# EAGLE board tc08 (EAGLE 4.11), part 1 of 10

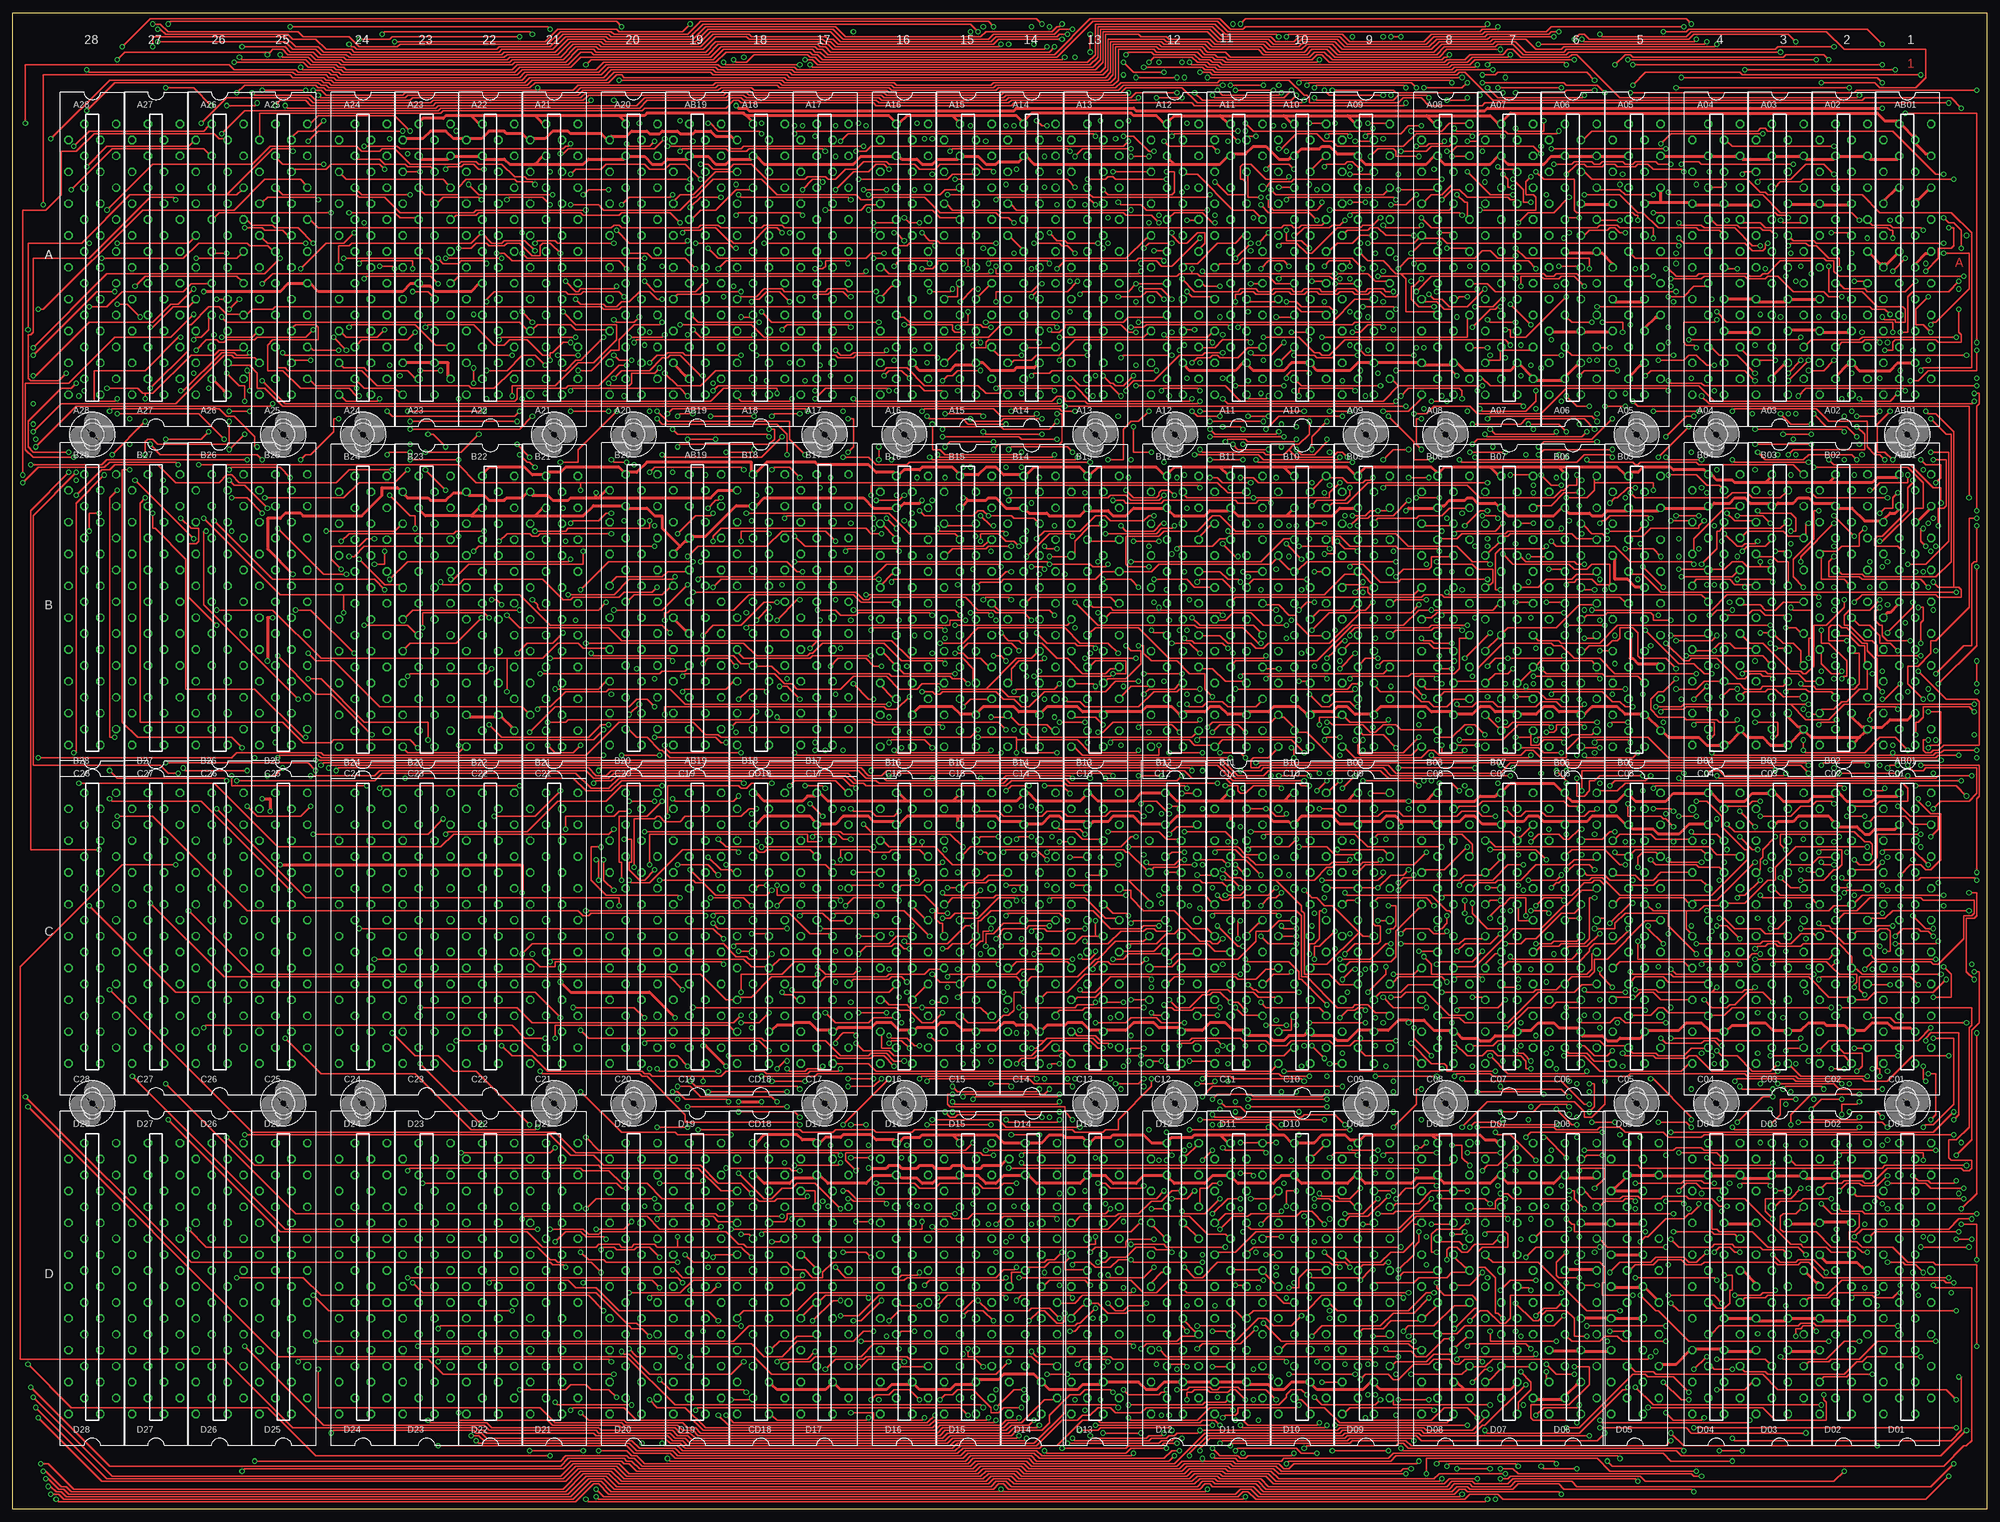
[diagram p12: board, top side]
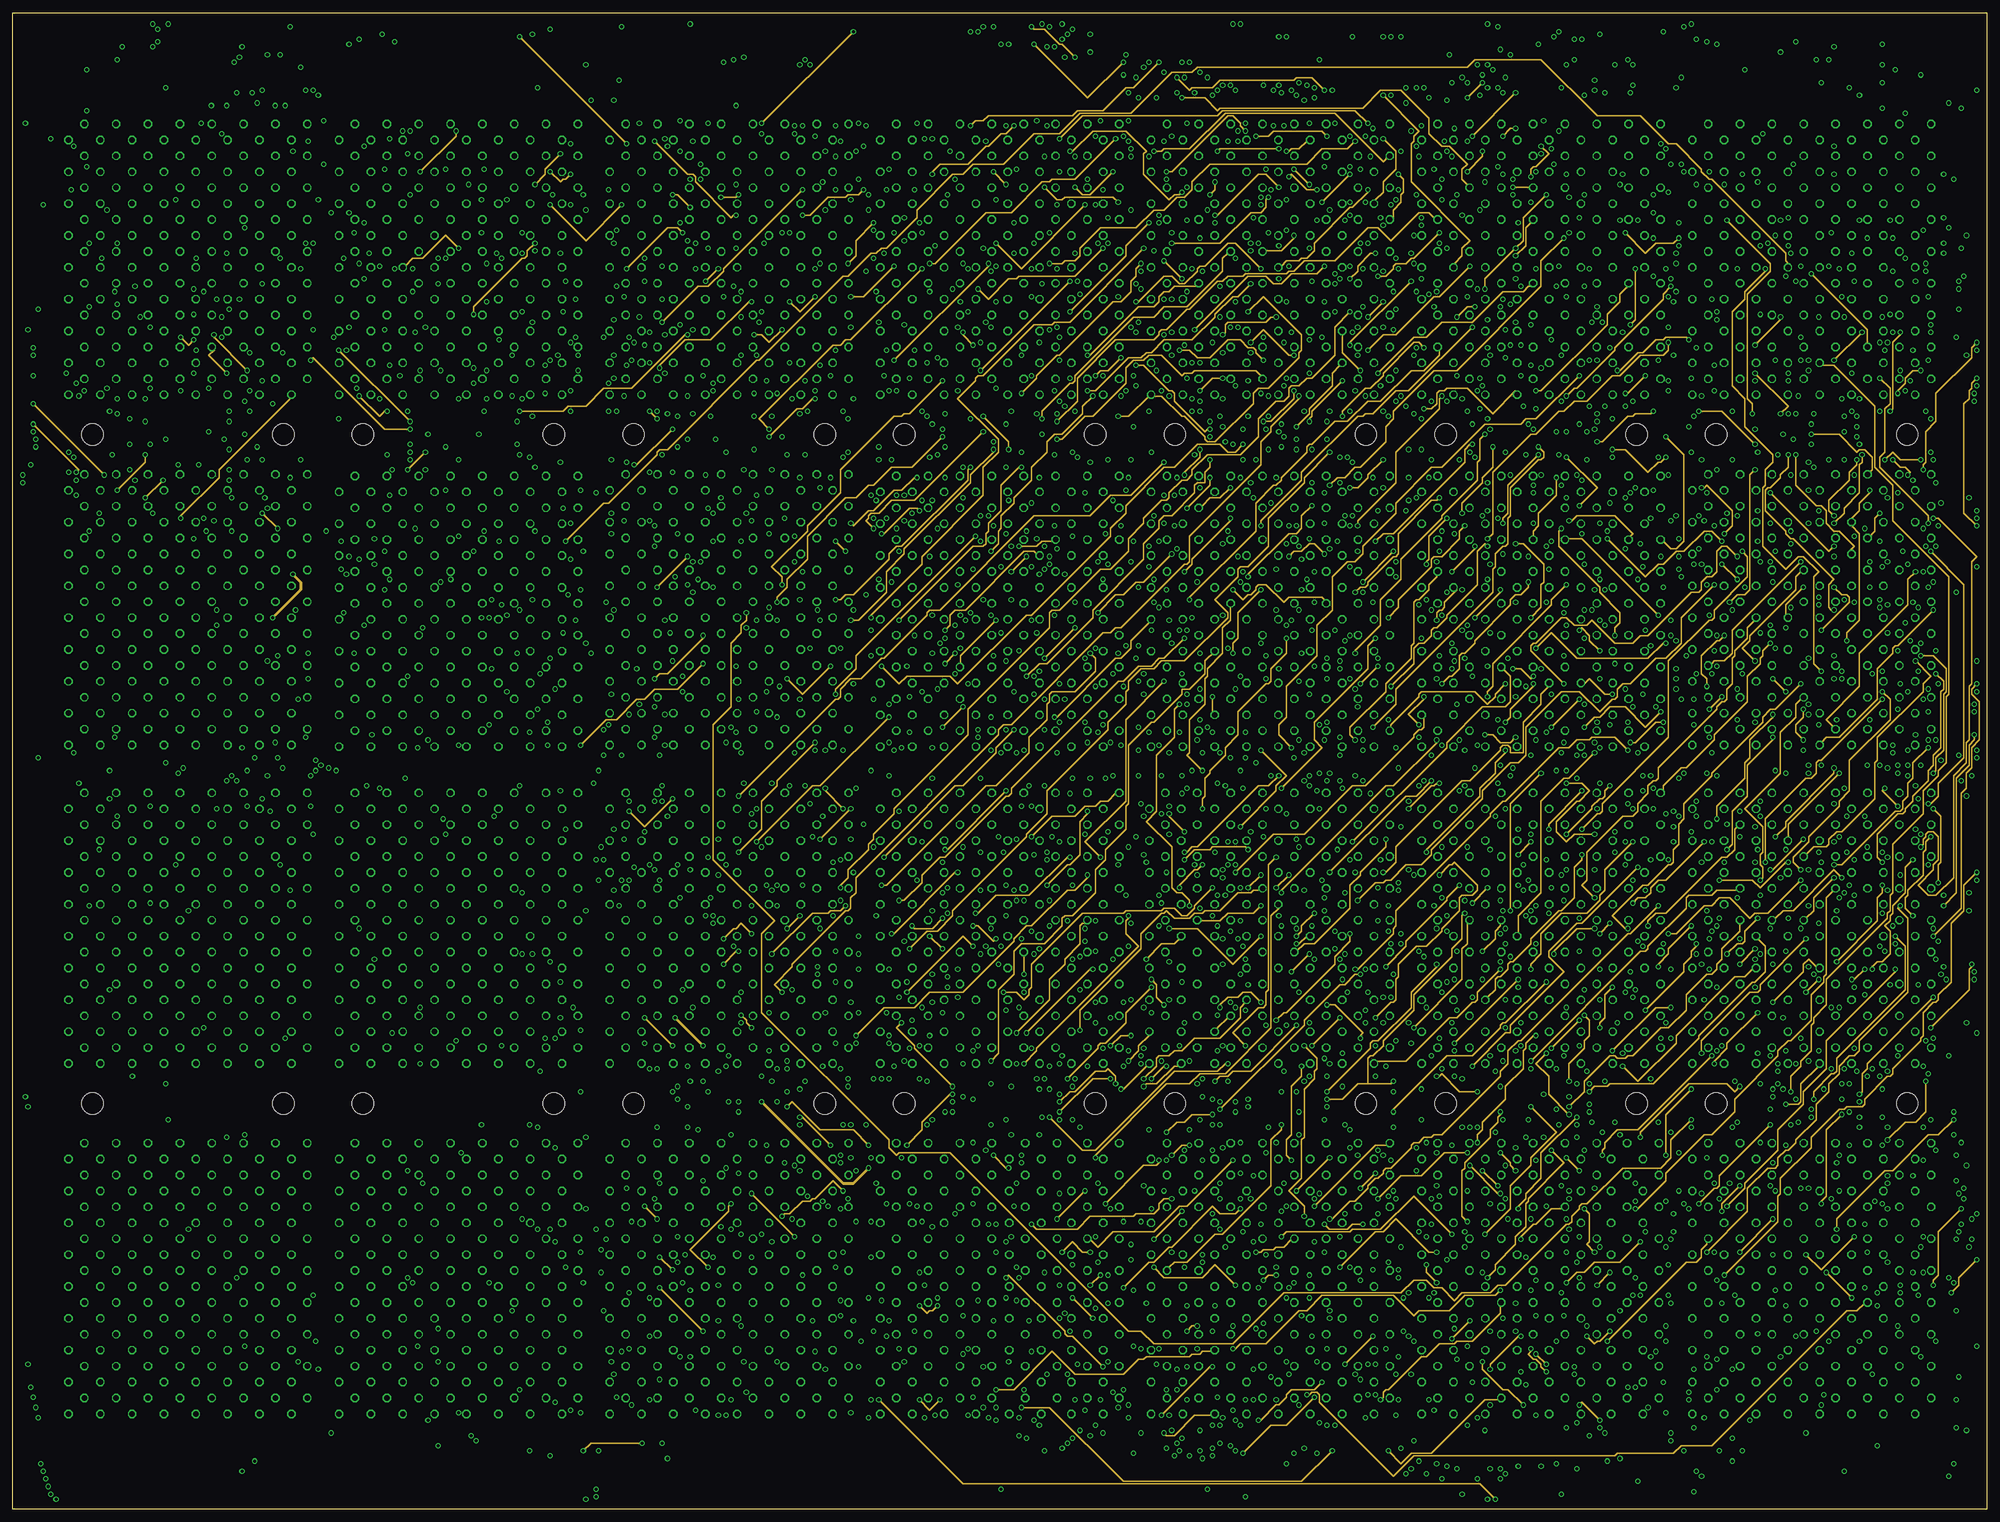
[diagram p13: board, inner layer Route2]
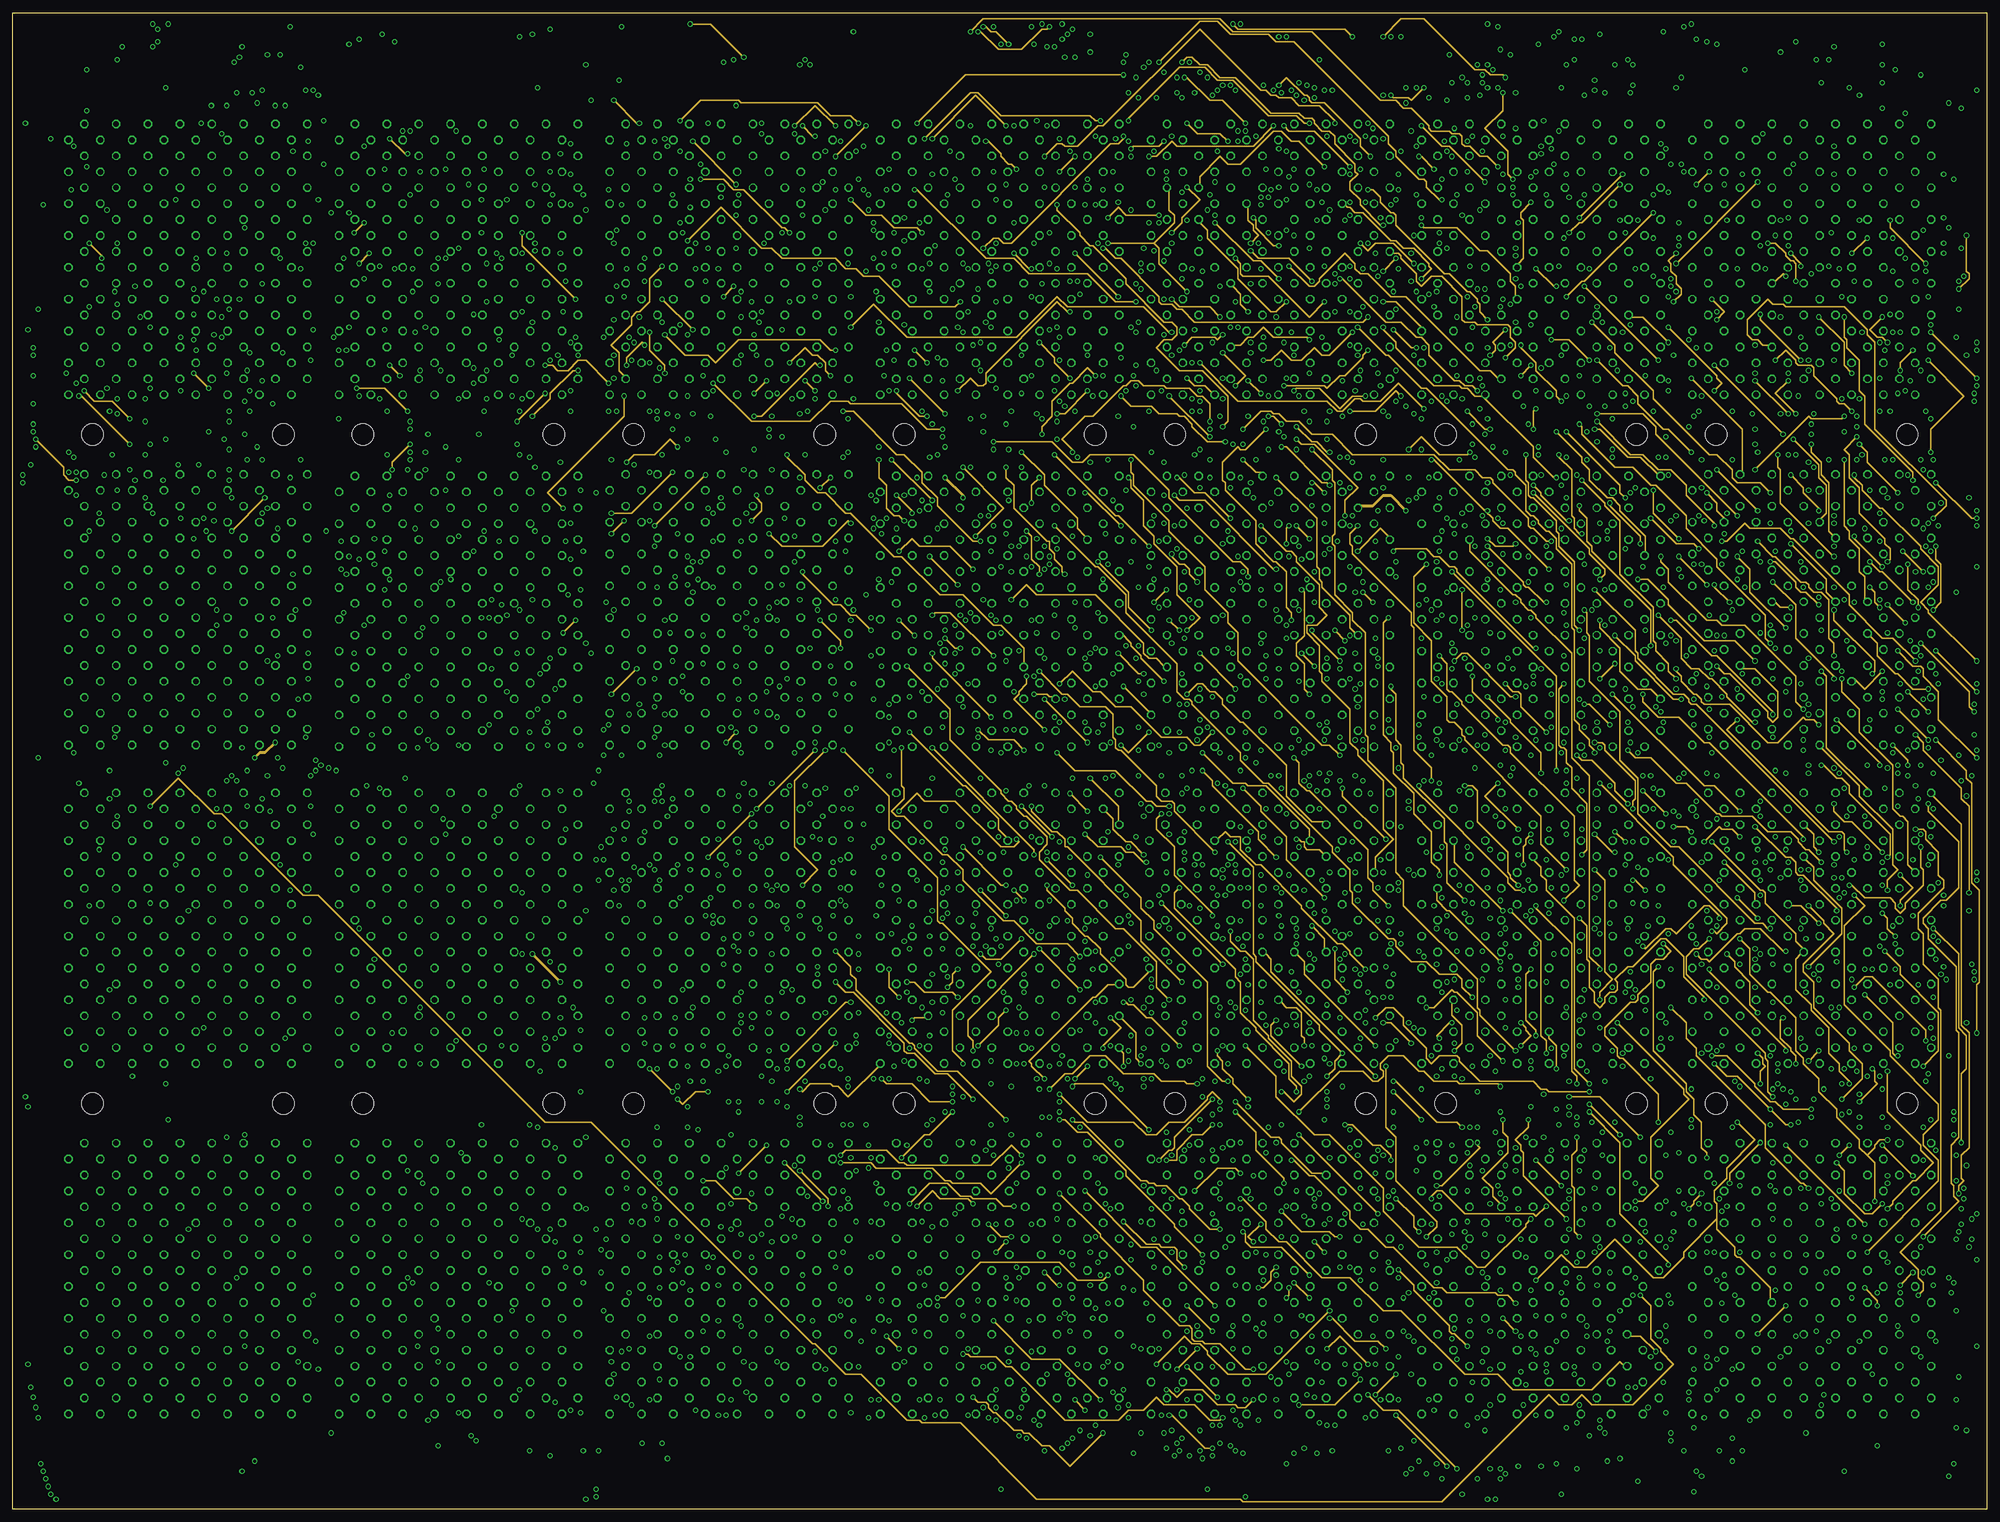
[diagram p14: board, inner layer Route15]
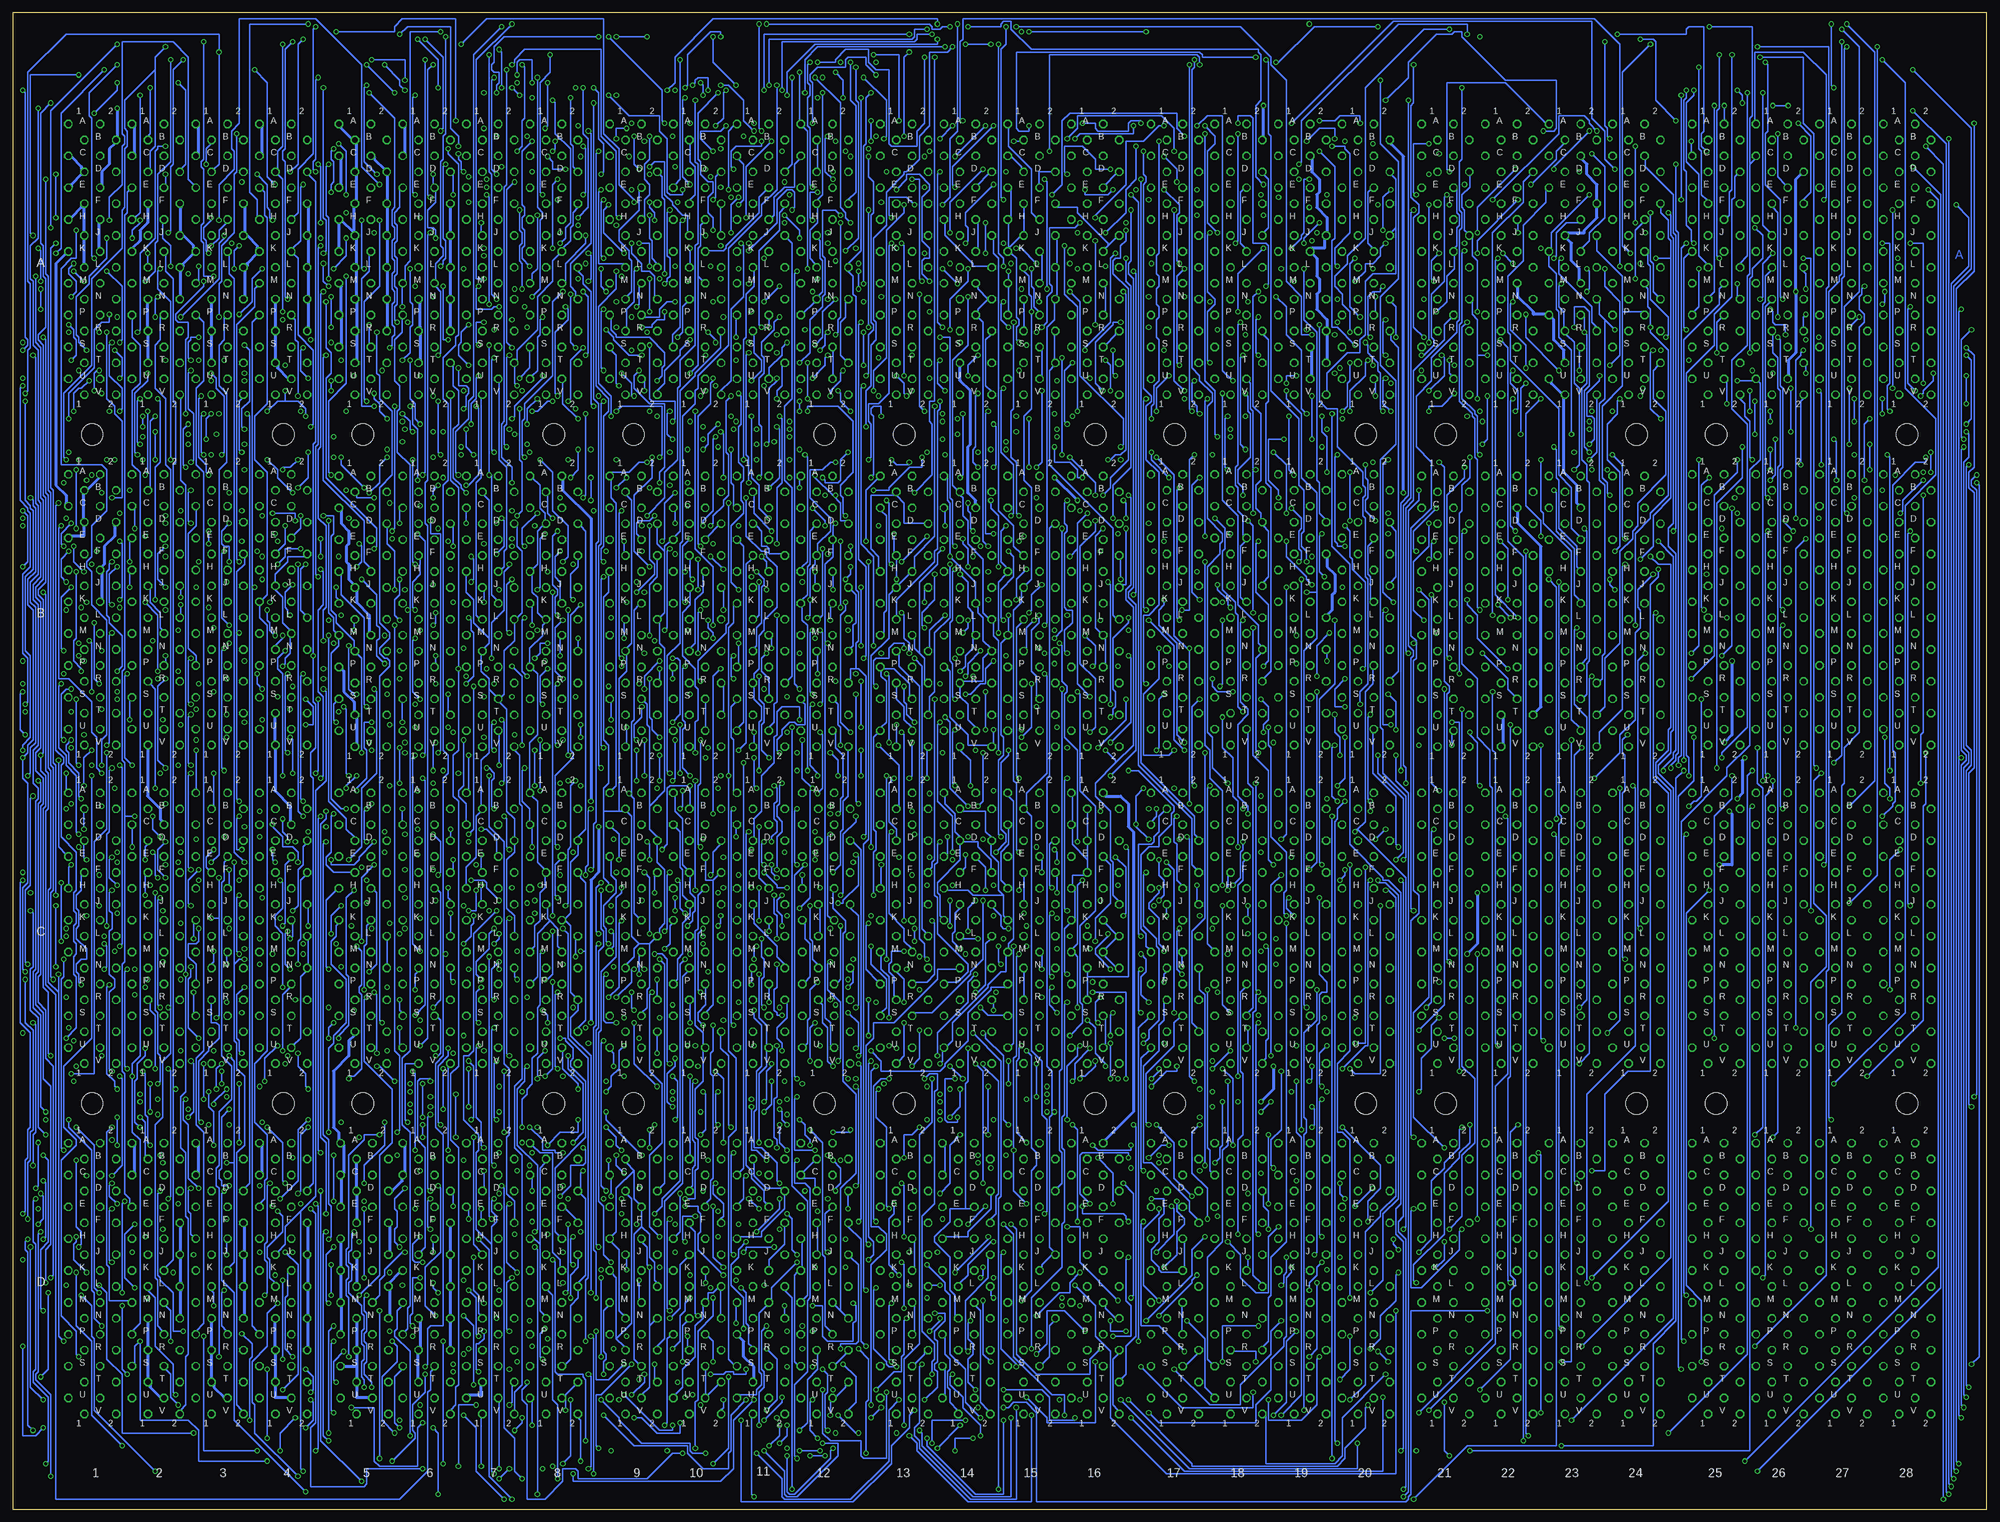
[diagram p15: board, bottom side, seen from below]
Size 393.76 x 298.44 mm. Coordinates in mm from the lower left corner, seen from the top.
Outline: 393.73,0 0,0 0.03,298.42 393.76,298.44 393.73,0
Copper layers (1*2*15*16): Top 0.035mm / dielectric 1.5mm / Route2 0.035mm / dielectric 0.15mm / Route15 0.035mm / dielectric 0.2mm / Bottom 0.035mm
Design rules "10mils": minimum track width 10mil, minimum drill 24mil, track to track 10mil, track to pad 10mil, pad to pad 10mil, via to via 10mil, smd to smd 10mil, copper to edge 40mil, drill to drill 10mil, minimum pad ring 10mil, minimum via ring 8mil, stop-mask expansion 0mil, vias tented up to drill 0mil, thermal gap 10mil
Net classes: 1 Power: width 0.635 mm, drill 0.381 mm, clearance 0.381 mm

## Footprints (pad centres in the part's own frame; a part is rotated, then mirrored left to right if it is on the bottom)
H807 = drill 1.092 octagon: A1 4.763,28.575; A2 -1.587,28.575; B1 1.587,25.4; B2 -4.763,25.4; C1 4.763,22.225; C2 -1.587,22.225; D1 1.587,19.05; D2 -4.763,19.05; E1 4.763,15.875; E2 -1.587,15.875; F1 1.587,12.7; F2 -4.763,12.7; H1 4.763,9.525; H2 -1.587,9.525; J1 1.587,6.35; J2 -4.763,6.35; K1 4.763,3.175; K2 -1.587,3.175; L1 1.587,0; L2 -4.763,0; M1 4.763,-3.175; M2 -1.587,-3.175; N1 1.587,-6.35; N2 -4.763,-6.35; P1 4.763,-9.525; P2 -1.587,-9.525; R1 1.587,-12.7; R2 -4.763,-12.7; S1 4.763,-15.875; S2 -1.587,-15.875; T1 1.587,-19.05; T2 -4.763,-19.05; U1 4.763,-22.225; U2 -1.587,-22.225; V1 1.587,-25.4; V2 -4.763,-25.4
H807-2 = drill 1.092 octagon: AA1 4.763,60.325; AA2 -1.587,60.325; AB1 1.587,57.15; AB2 -4.763,57.15; AC1 4.763,53.975; AC2 -1.587,53.975; AD1 1.587,50.8; AD2 -4.763,50.8; AE1 4.763,47.625; AE2 -1.587,47.625; AF1 1.587,44.45; AF2 -4.763,44.45; AH1 4.763,41.275; AH2 -1.587,41.275; AJ1 1.587,38.1; AJ2 -4.763,38.1; AK1 4.763,34.925; AK2 -1.587,34.925; AL1 1.587,31.75; AL2 -4.763,31.75; AM1 4.763,28.575; AM2 -1.587,28.575; AN1 1.587,25.4; AN2 -4.763,25.4; AP1 4.763,22.225; AP2 -1.587,22.225; AR1 1.587,19.05; AR2 -4.763,19.05; AS1 4.763,15.875; AS2 -1.587,15.875; AT1 1.587,12.7; AT2 -4.763,12.7; AU1 4.763,9.525; AU2 -1.587,9.525; AV1 1.587,6.35; AV2 -4.763,6.35; BA1 4.763,-9.525; BA2 -1.587,-9.525; BB1 1.587,-12.7; BB2 -4.763,-12.7; BC1 4.763,-15.875; BC2 -1.587,-15.875; BD1 1.587,-19.05; BD2 -4.763,-19.05; BE1 4.763,-22.225; BE2 -1.587,-22.225; BF1 1.587,-25.4; BF2 -4.763,-25.4; BH1 4.763,-28.575; BH2 -1.587,-28.575; BJ1 1.587,-31.75; BJ2 -4.763,-31.75; BK1 4.763,-34.925; BK2 -1.587,-34.925; BL1 1.587,-38.1; BL2 -4.763,-38.1; BM1 4.763,-41.275; BM2 -1.587,-41.275; BN1 1.587,-44.45; BN2 -4.763,-44.45; BP1 4.763,-47.625; BP2 -1.587,-47.625; BR1 1.587,-50.8; BR2 -4.763,-50.8; BS1 4.763,-53.975; BS2 -1.587,-53.975; BT1 1.587,-57.15; BT2 -4.763,-57.15; BU1 4.763,-60.325; BU2 -1.587,-60.325; BV1 1.587,-63.5; BV2 -4.763,-63.5
4,3 = hole 4.3: 0,0

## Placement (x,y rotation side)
A02  M903  [H807]  365.16,247.64 0 top
A03  M903  [H807]  352.46,247.64 0 top
A04  M903  [H807]  339.76,247.64 0 top
A05  M903  [H807]  323.89,247.64 0 top
A06  M903  [H807]  311.19,247.64 0 top
A07  M161  [H807]  298.49,247.64 0 top
A08  M206  [H807]  285.79,247.64 0 top
A09  M117  [H807]  269.91,247.64 0 top
A10  M113  [H807]  257.21,247.64 0 top
A11  M111  [H807]  244.51,247.64 0 top
A12  M113  [H807]  231.81,247.64 0 top
A13  H807  [H807]  215.94,247.64 0 top
A14  M302  [H807]  203.24,247.64 0 top
A15  M627  [H807]  190.54,247.64 0 top
A16  M602  [H807]  177.84,247.64 0 top
A17  H807  [H807]  161.96,247.64 0 top
A18  G888  [H807]  149.26,247.64 0 top
A20  G888  [H807]  123.86,247.64 0 top
A21  G888  [H807]  107.99,247.64 0 top
A22  M502  [H807]  95.29,247.64 0 top
A23  M633  [H807]  82.59,247.64 0 top
A24  W023  [H807]  69.89,247.64 0 top
A25  [H807]  54.01,247.64 0 top
A26  [H807]  41.31,247.64 0 top
A27  H807  [H807]  28.61,247.64 0 top
A28  H807  [H807]  15.91,247.64 0 top
AB01  G821  [H807-2]  377.86,215.89 0 top
AB19  W032  [H807-2]  136.56,215.89 0 top
B02  M623  [H807]  365.16,177.79 0 top
B03  M623  [H807]  352.46,177.79 0 top
B04  M623  [H807]  339.76,177.79 0 top
B05  M623  [H807]  323.89,177.47 0 top
B06  M111  [H807]  311.19,177.47 0 top
B07  M207  [H807]  298.49,177.47 0 top
B08  M113  [H807]  285.79,177.47 0 top
B09  M206  [H807]  269.91,177.47 0 top
B10  M627  [H807]  257.21,177.47 0 top
B11  M115  [H807]  244.51,177.47 0 top
B12  M117  [H807]  231.81,177.47 0 top
B13  M206  [H807]  215.94,177.47 0 top
B14  M206  [H807]  203.24,177.47 0 top
B15  M113  [H807]  190.54,177.47 0 top
B16  M602  [H807]  177.84,177.47 0 top
B17  H807  [H807]  161.96,177.79 0 top
B18  G888  [H807]  149.26,177.79 0 top
B20  G888  [H807]  123.86,177.79 0 top
B21  G879  [H807]  107.99,177.47 0 top
B22  M633  [H807]  95.29,177.47 0 top
B23  W005  [H807]  82.59,177.47 0 top
B24  H807  [H807]  69.89,177.47 0 top
B25  H807  [H807]  54.01,177.79 0 top
B26  H807  [H807]  41.31,177.79 0 top
B27  H807  [H807]  28.61,177.79 0 top
B28  H807  [H807]  15.91,177.79 0 top
C01  M101  [H807]  377.86,114.29 0 top
C02  M101  [H807]  365.16,114.29 0 top
C03  M101  [H807]  352.46,114.29 0 top
C04  M103  [H807]  339.76,114.29 0 top
C05  M103  [H807]  323.89,114.29 0 top
C06  M111  [H807]  311.19,114.29 0 top
C07  M207  [H807]  298.49,114.29 0 top
C08  M121  [H807]  285.79,114.29 0 top
C09  M206  [H807]  269.91,114.29 0 top
C10  M121  [H807]  257.21,114.29 0 top
C11  M113  [H807]  244.51,114.29 0 top
C12  M115  [H807]  231.49,114.29 0 top
C13  M111  [H807]  215.94,114.29 0 top
C14  M206  [H807]  203.24,114.29 0 top
C15  M113  [H807]  190.54,114.29 0 top
C16  M627  [H807]  177.84,114.29 0 top
C17  M111  [H807]  161.96,114.29 0 top
C19  H807  [H807]  136.56,114.29 0 top
C20  H807  [H807]  123.86,114.29 0 top
C21  H807  [H807]  107.99,114.29 0 top
C22  H807  [H807]  95.29,114.29 0 top
C23  H807  [H807]  82.59,114.29 0 top
C24  H807  [H807]  69.89,114.29 0 top
C25  H807  [H807]  54.01,114.29 0 top
C26  H807  [H807]  41.31,114.29 0 top
C27  H807  [H807]  28.61,114.29 0 top
C28  H807  [H807]  15.91,114.29 0 top
CD18  M228  [H807-2]  149.26,82.54 0 top
D01  H807  [H807]  377.86,44.44 0 top
D02  M903  [H807]  365.16,44.44 0 top
D03  M903  [H807]  352.46,44.44 0 top
D04  M903  [H807]  339.76,44.44 0 top
D05  M903  [H807]  323.57,44.44 0 top
D06  M903  [H807]  311.19,44.44 0 top
D07  M161  [H807]  298.49,44.44 0 top
D08  M207  [H807]  285.79,44.44 0 top
D09  M121  [H807]  269.91,44.44 0 top
D10  M119  [H807]  257.21,44.44 0 top
D11  M206  [H807]  244.51,44.44 0 top
D12  M627  [H807]  231.81,44.44 0 top
D13  M602  [H807]  215.94,44.44 0 top
D14  M307  [H807]  203.55,44.44 0 top
D15  M401  [H807]  190.54,44.44 0 top
D16  M302  [H807]  177.84,44.44 0 top
D17  M602  [H807]  161.96,44.44 0 top
D19  H807  [H807]  136.56,44.44 0 top
D20  H807  [H807]  123.86,44.44 0 top
D21  H807  [H807]  107.99,44.44 0 top
D22  H807  [H807]  95.29,44.44 0 top
D23  H807  [H807]  82.59,44.44 0 top
D24  H807  [H807]  69.89,44.44 0 top
D25  H807  [H807]  54.01,44.44 0 top
D26  H807  [H807]  41.31,44.44 0 top
D27  H807  [H807]  28.61,44.44 0 top
D28  H807  [H807]  15.91,44.44 0 top
U$17  [4,3]  54.01,214.3 0 top
U$18  [4,3]  69.89,214.3 0 top
U$19  [4,3]  107.99,214.3 0 top
U$20  [4,3]  123.86,214.3 0 top
U$66  [4,3]  161.96,214.3 0 top
U$67  [4,3]  177.84,214.3 0 top
U$68  [4,3]  215.94,214.3 0 top
U$69  [4,3]  231.81,214.3 0 top
U$70  [4,3]  269.91,214.3 0 top
U$71  [4,3]  285.79,214.3 0 top
U$72  [4,3]  323.89,214.3 0 top
U$73  [4,3]  339.76,214.3 0 top
U$74  [4,3]  377.86,214.3 0 top
U$75  [4,3]  377.86,80.95 0 top
U$76  [4,3]  339.76,80.95 0 top
U$77  [4,3]  323.89,80.95 0 top
U$78  [4,3]  285.79,80.95 0 top
U$79  [4,3]  269.91,80.95 0 top
U$80  [4,3]  231.81,80.95 0 top
U$81  [4,3]  215.94,80.95 0 top
U$82  [4,3]  177.84,80.95 0 top
U$83  [4,3]  161.96,80.95 0 top
U$84  [4,3]  107.99,80.95 0 top
U$85  [4,3]  69.89,80.95 0 top
U$86  [4,3]  123.86,80.95 0 top
U$87  [4,3]  54.01,80.95 0 top
U$88  [4,3]  15.91,80.95 0 top
U$90  [4,3]  15.91,214.3 0 top

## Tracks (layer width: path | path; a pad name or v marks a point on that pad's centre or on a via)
00\  (via drill 0.61)
  Top 0.254: v100.62,170.68 102.65,172.71 107.73,172.71 v109.76,174.74 | v111.29,196.58 111.8,197.09 116.88,197.09 118.4,198.62 v119.42,198.62 | v132.62,217.92 133.13,218.43 v135.67,218.43 | v296.2,267.7 296.71,267.2 299.76,267.2 A07.D1
  Route2 0.254: v149.39,276.34 v167.68,294.63
  Route15 0.254: v109.76,174.74 v112.3,177.28 | v119.42,198.62 123.48,198.62 v131.61,206.74 | v141.77,241.8 v143.8,243.83 | v191.04,294.63 193.58,297.17 240.83,297.17 243.37,294.63 259.12,294.63 272.83,280.91 275.88,280.91 277.4,279.39 278.93,279.39 282.48,275.83 282.48,275.32 282.99,274.82 286.55,274.82 287.06,274.31 288.58,274.31 289.09,273.8 289.09,272.28 289.6,271.77 290.61,271.77 292.64,269.74 294.17,269.74 v296.2,267.7
  Bottom 0.254: v100.62,170.68 95.54,165.6 95.54,163.56 94.02,162.04 B22.S2 | v112.3,177.28 114.34,179.31 114.34,188.96 111.29,192.01 v111.29,196.58 | v131.61,206.74 131.61,213.86 132.62,214.87 v132.62,217.92 | v135.67,218.43 136.69,219.44 136.69,231.13 139.74,234.18 139.74,239.76 v141.77,241.8 | v143.8,243.83 143.29,244.34 143.29,251.96 143.8,252.46 146.34,252.46 146.34,277.36 146.85,277.86 149.39,277.86 v149.39,276.34 | v167.68,294.63 v191.04,294.63
0_TO_AC\  (via drill 0.61)
  Top 0.254: v306.87,162.55 307.38,163.06 317.03,163.06 319.06,161.02 320.58,161.02 321.6,160.01 v323.12,160.01
  Bottom 0.254: v306.87,162.55 306.87,158.99 B06.T2 | v323.12,160.01 323.63,160.52 323.63,177.79 328.2,182.36 328.2,186.42 B05.H1
0_TO_DTB  (via drill 0.61)
  Top 0.254: v225.59,85.84 224.57,84.82 v220,84.82 | v208.82,81.27 208.32,80.76 188,80.76 v187.49,81.27 | v173.26,85.84 171.74,84.32 v166.66,84.32 | v161.58,88.38 161.07,87.87 158.53,87.87 158.02,87.36 154.98,87.36 v154.47,87.87 | v150.91,91.43 148.88,93.46 126.53,93.46 v126.02,92.95 | v123.99,128 123.99,137.66 128.05,137.66 128.56,138.16 129.07,138.16 130.08,137.15 133.13,137.15 134.15,138.16 145.32,138.16 146.85,139.69 v148.37,139.69 | v195.62,211.32 196.63,212.33 208.82,212.33 209.33,212.84 209.33,218.43 v208.32,218.43 | v246.92,244.34 248.96,244.34 A11.M1
  Route2 0.254: v225.59,85.84 228.13,88.38 228.13,89.9 228.64,90.41 230.67,90.41 231.68,91.43 233.21,91.43 235.75,93.97 240.83,93.97 244.89,98.03 244.89,100.06 245.91,101.08 C11.R1 | v220,84.82 220,86.35 218.48,87.87 217.97,87.36 215.94,87.36 211.87,83.3 210.86,83.3 v208.82,81.27 | v167.17,177.28 168.69,177.28 174.28,182.87 174.28,186.93 177.84,190.49 177.84,191.5 191.04,204.71 191.04,206.24 195.62,210.81 v195.62,211.32 | v214.41,223 215.94,223 222.54,229.6 225.08,229.6 226.1,230.62 227.11,230.62 229.65,233.16 235.24,233.16 239.81,237.73 239.81,238.24 243.37,241.8 244.38,241.8 v246.92,244.34
  Route15 0.254: v187.49,81.27 182.92,81.27 179.36,84.82 174.28,84.82 v173.26,85.84 | v148.37,139.69 v160.06,151.37 | v208.32,218.43 209.84,218.43 v214.41,223
  Bottom 0.254: v166.66,84.32 163.61,87.36 161.58,87.36 v161.58,88.38 | v154.47,87.87 v150.91,91.43 | v126.02,92.95 123.99,92.95 v123.99,128 | v160.06,151.37 162.09,153.4 162.09,172.2 v167.17,177.28
0_TO_DTB\  (via drill 0.61)
  Top 0.254: B10.L1 260.64,179.31 266.74,179.31 267.75,180.33 B09.K2 | v270.8,142.74 274.36,142.74 C09.A1 | v247.94,209.28 248.45,208.78 v267.24,208.78
  Bottom 0.254: 270.29,142.23 v270.8,142.74 | 270.29,142.23 269.78,141.72 269.78,118.86 268.77,117.84 C09.K2 | C09.A1 274.36,143.24 273.34,144.26 273.34,200.65 274.36,201.66 274.36,205.73 B09.A1 274.36,206.74 270.8,206.74 268.77,208.78 v267.24,208.78 | v247.94,209.28 247.94,233.16 247.43,233.67 247.43,242.3 245.91,243.83 245.91,246.88 A11.L1 | 270.29,142.23 270.29,156.96 269.78,157.47 269.78,179.31 268.77,180.33 B09.K2
0_TO_EF
  Bottom 0.254: A11.E2 243.37,263.13 244.89,261.61 244.89,258.56 251.5,251.96 251.5,251.45 252,250.94 255.05,250.94 A10.K2
0_TO_EF\  (via drill 0.61)
  Top 0.254: 287.06,236.72 287.06,239.26 285.53,239.26 284.01,240.78 281.47,240.78 A08.N2 | 287.06,236.72 287.06,235.7 A08.R1 | v244.38,235.7 244.89,236.21 267.24,236.21 267.75,236.72 287.06,236.72 | v278.93,274.82 285.02,274.82 286.55,276.34 290.1,276.34 A08.A1
  Bottom 0.254: v244.38,235.7 244.89,236.21 244.89,250.94 240.83,255 240.83,258.56 239.81,259.58 A11.F2 | v278.93,274.82 278.42,274.31 278.42,252.46 282.48,248.4 282.48,243.83 281.47,242.81 281.47,241.8 A08.N2
0_TO_LPB\  (via drill 0.61)
  Top 0.254: v228.64,31.99 230.16,30.47 v276.39,30.47 | v276.39,46.22 277.4,47.23 283.5,47.23 D08.K2
  Bottom 0.254: v228.64,31.99 228.64,33.01 225.59,33.01 225.08,33.52 225.08,48.76 226.6,50.28 D12.J2 | v276.39,30.47 v276.39,46.22 | D08.A1 290.1,72.63 288.58,71.11 286.04,71.11 286.04,51.3 284.52,49.77 284.52,48.25 D08.K2
0_TO_STA
  Top 0.254: A11.N1 246.42,240.78 252,240.78 A10.N2
0_TO_STA\  (via drill 0.61)
  Top 0.254: B11.P2 243.37,168.64 243.88,169.15 260.13,169.15 267.24,176.26 277.4,176.26 280.45,179.31 v282.99,179.31 295.18,179.31 296.2,180.33 B07.K2 | v302.8,150.36 302.3,149.85 283.5,149.85 v282.99,150.36 | v298.74,206.24 302.8,206.24 B07.A1 | v249.46,233.67 256.58,233.67 259.62,230.62 260.64,230.62 261.15,230.11 262.67,230.11 265.72,233.16 297.72,233.16 v298.74,232.14
  Bottom 0.254: v302.8,150.36 302.8,143.24 C07.A1 | v282.99,179.31 v282.99,150.36 | B07.K2 297.22,181.34 298.23,182.36 298.23,206.24 v298.74,206.24 v298.74,232.14 | v249.46,233.67 249.46,237.73 A11.P1
0_TO_STATE\  (via drill 0.61)
  Top 0.254: v143.8,112.26 144.31,112.76 174.79,112.76 176.31,114.29 C16.L1
  Bottom 0.254: v143.8,112.26 143.29,111.75 143.29,93.97 143.8,93.46 143.8,89.9 144.31,89.4 CD18.AV2
0_TO_W\  (via drill 0.61)
  Top 0.254: v145.32,54.85 146.85,54.85 147.36,54.34 CD18.BH2 | v145.32,97.02 148.88,97.02 v150.91,99.05 | v152.44,120.38 153.96,121.91 164.63,121.91 v165.14,121.4 | v165.14,129.53 165.14,131.56 170.72,131.56 171.23,131.05 174.79,131.05 175.3,131.56 180.88,131.56 181.9,130.54 C16.E1
  Bottom 0.254: v145.32,54.85 145.83,55.36 145.83,96.51 v145.32,97.02 | v150.91,99.05 152.44,100.57 v152.44,120.38 | v165.14,121.4 164.12,122.42 164.12,125.46 165.14,126.48 v165.14,129.53
01\  (via drill 0.61)
  Top 0.254: v79.79,242.81 82.84,242.81 83.86,241.8 A23.N1 | v79.79,247.38 79.79,248.91 69.63,248.91 v69.12,248.4 | v67.09,292.09 67.6,291.58 68.11,291.58 68.62,291.07 96.56,291.07 97.06,291.58 107.22,291.58 109.76,294.12 118.91,294.12 119.42,293.61 135.16,293.61 137.7,296.15 191.04,296.15 v192.57,294.63 | v297.22,266.18 298.23,265.16 298.23,263.64 v299.25,263.64
  Route2 0.254: v299.25,263.64 302.8,263.64 A07.E1
  Route15 0.254: v71.16,250.43 v69.12,248.4 | v192.57,294.63 193.08,294.63 196.63,291.07 201.2,291.07 205.27,295.14 206.28,295.14 v206.79,295.64 | v243.37,296.15 244.38,295.14 265.72,295.14 v267.24,293.61 | v273.34,293.61 276.9,297.17 281.47,297.17 291.63,287.01 293.66,287.01 294.68,285.99 297.22,285.99 v297.72,285.48
  Bottom 0.254: v79.79,242.81 79.28,243.32 79.28,246.88 v79.79,247.38 | v71.16,250.43 72.68,251.96 72.68,286.5 v67.09,292.09 | v206.79,295.64 208.32,295.64 208.82,295.14 210.35,295.14 210.35,295.64 210.86,296.15 v243.37,296.15 | v267.24,293.61 v273.34,293.61 | v297.72,285.48 298.23,284.98 298.23,267.2 v297.22,266.18
1_TO_DF  (via drill 0.61)
  Top 0.254: v238.29,4.05 237.78,3.54 197.65,3.54 | 197.65,3.54 v197.14,4.05 | v215.43,107.68 215.43,108.19 216.44,109.21 218.48,109.21 218.98,108.7 225.08,108.7 v226.1,109.72 | v288.07,262.12 289.6,260.59 290.1,260.59 290.1,257.54 A08.H1 | v286.55,290.06 286.04,289.55 285.53,289.55 285.02,289.04 263.18,289.04 261.66,290.56 259.62,290.56 258.61,289.55 242.86,289.55 241.84,290.56 238.29,290.56 237.27,291.58 229.14,291.58 228.64,292.09 219.49,292.09 219.49,285.99 218.48,284.98 154.47,284.98 153.96,285.48 121.96,285.48 121.45,285.99 120.43,285.99 118.91,284.47 104.18,284.47 103.16,283.45 63.03,283.45 62.52,283.96 61.5,283.96 61,284.47 20.36,284.47 v14.77,278.88 | v7.66,3.04 9.18,3.04 10.2,2.02 111.8,2.02 115.35,5.58 117.38,5.58 119.42,3.54 197.65,3.54
  Route2 0.254: v202.22,94.98 214.92,107.68 v215.43,107.68 | v226.1,109.72 229.14,112.76 231.68,112.76 232.7,113.78 C12.L1
  Bottom 0.254: v238.29,4.05 238.29,42.15 239.81,43.68 D11.L2 | v197.14,4.05 197.14,61.96 196.63,62.47 196.63,89.4 v202.22,94.98 | C12.J1 232.7,119.88 232.7,114.8 C12.L1 | v288.07,262.12 288.58,262.62 288.58,284.47 286.55,286.5 v286.55,290.06 | v14.77,278.88 8.16,272.28 8.16,3.54 v7.66,3.04
1_TO_DTF  (via drill 0.61)
  Top 0.254: v239.3,28.44 242.35,28.44 D11.S2 | v217.46,15.23 v225.08,15.23 | v177.84,29.45 177.33,29.96 170.72,29.96 169.2,28.44 v168.69,28.44 | v146.34,23.36 145.83,23.86 131.1,23.86 v129.07,25.9 | v127.04,34.53 125.51,36.06 123.48,36.06 122.97,36.56 85.38,36.56 v84.87,36.06 | v85.38,184.9 85.89,184.39 88.94,184.39 89.95,185.41 105.7,185.41 109.76,181.34 111.29,181.34 111.8,181.85 120.94,181.85 121.96,182.87 127.54,182.87 v128.56,183.88 | v134.66,189.98 136.69,192.01 150.4,192.01 153.45,195.06 162.09,195.06 v164.12,193.03 | v166.15,191 166.66,191.5 176.31,191.5 v176.82,191 | v193.58,181.34 194.09,181.85 198.66,181.85 v199.17,181.34
  Route2 0.254: v239.3,28.44 238.8,28.44 v229.14,18.78 | v128.56,183.88 v134.66,189.98 | v164.12,193.03 v166.15,191
  Route15 0.254: v217.46,15.23 210.86,8.62 206.79,12.69 205.27,12.69 202.73,15.23 201.71,15.23 201.2,15.74 199.68,15.74 196.12,19.29 195.62,19.29 194.6,20.31 194.6,20.82 194.09,21.32 192.57,21.32 v191.55,22.34 | v176.82,191 179.36,193.54 180.88,192.01 186.98,192.01 v191.55,187.44 | v199.17,181.34 202.22,184.39 204.25,182.36 215.94,182.36 225.59,172.71 225.59,170.68 226.6,169.66 228.13,169.66 229.65,168.14 B12.P2
  Bottom 0.254: v229.14,18.78 225.59,15.23 v225.08,15.23 | v191.55,22.34 187.49,18.28 187.49,17.26 177.84,17.26 v177.84,29.45 | v168.69,28.44 160.56,20.31 146.34,20.31 v146.34,23.36 | v129.07,25.9 127.04,27.93 v127.04,34.53 | v84.87,36.06 85.38,36.56 85.38,136.64 84.87,137.15 84.87,138.16 85.38,138.67 v85.38,184.9 | v191.55,187.44 193.58,185.41 v193.58,181.34
02\  (via drill 0.61)
  Top 0.254: v300.26,256.53 302.3,258.56 307.38,258.56 v310.42,261.61 | v309.92,288.02 309.41,288.53 294.68,288.53 v294.17,288.02 | v272.83,257.54 271.31,256.02 269.28,256.02 268.77,255.51 264.2,255.51 259.12,250.43 258.1,250.43 256.07,252.46 253.02,252.46 v252.51,251.96 | v81.32,266.69 A23.D2
  Route2 0.254: v88.43,274.82 88.43,273.8 v81.32,266.69
  Route15 0.254: v252.51,251.96 251.5,251.96 247.94,255.51 247.94,257.04 v247.43,257.54 | v242.35,272.78 240.83,274.31 236.26,274.31 v234.22,276.34 | v221.52,285.99 190.03,285.99 v180.38,276.34 | v168.69,276.34 167.17,277.86 163.1,277.86 160.56,280.4 145.32,280.4 144.82,280.91 137.2,280.91 v133.13,276.85 | v125,276.34 124.5,276.34 v119.92,280.91
  Bottom 0.254: v300.26,256.53 300.26,254.5 A07.J1 | v310.42,261.61 310.93,262.12 310.93,287.01 v309.92,288.02 | v294.17,288.02 293.66,288.53 293.66,289.04 291.63,291.07 276.39,291.07 276.39,273.8 273.34,270.75 273.34,258.05 v272.83,257.54 | v247.43,257.54 247.43,267.7 v242.35,272.78 | v234.22,276.34 234.22,284.47 234.73,284.98 234.73,285.99 233.21,287.52 227.62,287.52 227.62,289.04 227.11,289.55 223.56,289.55 223.56,288.02 v221.52,285.99 | v180.38,276.34 177.84,276.34 177.84,275.32 177.33,274.82 171.23,274.82 171.23,276.34 170.72,276.85 168.69,276.85 v168.69,276.34 | v133.13,276.85 130.08,276.85 129.07,277.86 125,277.86 v125,276.34 | v119.92,280.91 115.35,285.48 115.35,288.53 109.76,294.12 106.72,294.12 106.21,294.63 104.68,294.63 104.68,293.61 96.05,284.98 85.89,284.98 85.89,275.32 86.4,274.82 v88.43,274.82
03\  (via drill 0.61)
  Top 0.254: v280.96,256.02 280.45,255.51 273.85,255.51 v273.34,256.02 | v130.08,273.29 128.05,271.26 110.78,271.26 109.76,270.24 v109.26,270.24 | v104.18,264.15 103.67,264.66 100.62,264.66 100.11,265.16 90.46,265.16 88.94,263.64 88.94,262.12 82.33,262.12 81.32,263.13 A23.E2
  Route2 0.254: v211.87,289.55 209.33,292.09 208.82,292.09 205.78,295.14 203.74,295.14 v203.24,295.64 | v109.26,270.24 106.21,267.2 106.21,266.18 v104.18,264.15
  Route15 0.254: v280.96,256.02 281.47,255.51 288.07,255.51 292.64,250.94 294.17,250.94 298.74,246.37 298.74,244.84 299.76,243.83 299.76,241.8 A07.N1 | v273.34,256.02 272.83,256.02 268.77,260.08 268.77,261.1 266.74,263.13 266.74,264.66 268.26,266.18 267.75,266.69 267.75,268.21 263.69,272.28 263.69,273.8 262.67,274.82 261.15,274.82 259.62,276.34 259.62,276.85 259.12,277.36 257.59,277.36 256.58,278.37 250.99,278.37 243.88,285.48 240.83,285.48 238.29,288.02 236.76,288.02 235.24,289.55 234.22,289.55 v233.21,288.53 | v144.31,264.15 v135.67,272.78
  Bottom 0.254: v233.21,288.53 229.65,288.53 229.65,289.04 227.62,291.07 223.05,291.07 223.05,288.53 221.52,287.01 218.98,287.01 218.98,272.28 218.48,271.77 213.4,271.77 213.4,274.82 211.87,276.34 v211.87,289.55 | v203.24,295.64 196.63,295.64 196.63,296.15 196.12,296.66 194.6,296.66 194.6,295.14 190.54,291.07 145.32,291.07 145.32,290.56 144.82,290.06 144.82,280.91 145.83,279.9 145.83,265.67 v144.31,264.15 | v135.67,272.78 133.13,275.32 130.08,275.32 v130.08,273.29
04\  (via drill 0.61)
  Top 0.254: v76.24,292.6 106.21,292.6 108.75,295.14 120.43,295.14 120.94,294.63 133.64,294.63 v135.16,296.15 | v285.02,261.1 287.06,263.13 288.58,263.13 290.1,261.61 298.23,261.61 298.74,261.1 299.76,261.1 A07.F1
  Route2 0.254: v191.04,275.83 192.06,276.85 193.58,276.85 194.6,277.86 211.36,277.86 212.38,278.88 217.46,278.88 222.03,283.45 223.56,283.45 v228.64,288.53
  Route15 0.254: v78.78,270.24 78.27,270.24 v75.22,273.29 | v135.16,296.15 139.23,296.15 v145.83,289.55 | v228.64,288.53 236.76,296.66 240.32,296.66 242.86,294.12 250.48,294.12 252,292.6 255.56,292.6 274.36,273.8 274.36,272.28 275.88,270.75 275.88,269.74 280.45,265.16 281.47,265.16 281.98,264.66 281.98,263.64 284.52,261.1 v285.02,261.1
  Bottom 0.254: v78.78,270.24 76.24,267.7 76.24,257.54 79.28,254.5 79.28,252.97 80.81,251.45 A23.K2 | v75.22,273.29 75.73,273.8 75.73,275.32 76.24,275.83 v76.24,292.6 | v145.83,289.55 156.5,289.55 156.5,290.06 157.01,290.56 193.58,290.56 193.58,275.32 193.08,274.82 191.04,274.82 v191.04,275.83
05\  (via drill 0.61)
  Top 0.254: v249.46,216.9 v238.8,216.9 | v211.36,210.81 210.35,211.82 199.17,211.82 v198.66,211.32 | v193.58,217.92 193.08,218.43 v185.96,218.43 | v178.85,225.54 177.33,227.06 174.79,227.06 v173.77,226.05 | v174.28,231.13 173.77,230.62 167.68,230.62 167.17,230.11 165.14,230.11 v164.12,231.13 | v130.08,234.18 129.58,233.67 v122.97,233.67 | v120.43,243.83 119.92,243.32 113.32,243.32 112.81,242.81 112.3,242.81 v110.27,244.84 | v109.26,250.43 107.22,252.46 105.7,252.46 105.19,251.96 105.19,249.92 103.67,249.92 101.13,252.46 98.59,252.46 98.08,251.96 95.03,251.96 94.52,252.46 92.49,252.46 91.48,251.45 v88.94,251.45
  Route2 0.254: v272.32,226.56 279.44,233.67 281.98,233.67 285.02,236.72 291.12,236.72 297.22,242.81 301.28,242.81 302.3,243.83 302.8,243.83 A07.M1 | v255.56,223 255.56,221.48 250.99,216.9 v249.46,216.9 | v198.66,211.32 198.66,212.84 v193.58,217.92 | v88.94,251.45 86.4,253.99 81.82,249.42 79.79,249.42 78.27,247.89 A23.L2
  Route15 0.254: v269.78,221.98 267.24,221.98 264.7,219.44 260.64,223.51 256.07,223.51 v255.56,223 | v238.8,216.9 238.8,220.46 237.27,221.98 236.26,221.98 234.73,223.51 230.16,223.51 229.65,224.02 225.59,224.02 224.57,225.03 223.05,225.03 222.03,224.02 221.52,224.02 215.43,217.92 213.9,217.92 209.33,213.35 211.36,211.32 v211.36,210.81 | v185.96,218.43 v178.85,225.54 | v164.12,231.13 163.1,231.13 161.07,233.16 144.82,233.16 140.24,228.59 138.72,230.11 134.15,230.11 v130.08,234.18
  Bottom 0.254: v272.32,226.56 270.29,224.52 270.29,221.98 v269.78,221.98 | v173.77,226.05 174.28,226.56 v174.28,231.13 | v122.97,233.67 123.48,234.18 123.48,241.8 122.46,242.81 120.94,242.81 120.94,243.32 v120.43,243.83 | v110.27,244.84 110.78,245.35 110.78,248.91 v109.26,250.43
06\  (via drill 0.61)
  Top 0.254: v84.87,249.42 85.89,248.4 88.94,248.4 89.44,248.91 94.02,248.91 v94.52,248.4 | v96.56,250.43 98.08,250.43 99.6,248.91 120.94,248.91 v122.46,247.38 | v133.64,254.5 134.15,255 137.2,255 137.7,255.51 140.24,255.51 142.78,252.97 143.29,252.97 143.8,252.46 147.36,252.46 150.4,255.51 152.44,255.51 v153.45,254.5 | v177.84,257.54 178.85,256.53 v180.88,256.53 | v188.5,235.7 189.01,236.21 193.08,236.21 193.58,235.7 v195.11,235.7 | v196.12,240.78 196.12,242.81 203.24,242.81 204.76,244.34 v205.27,244.34 | v208.32,247.38 209.84,248.91 224.06,248.91 224.57,249.42 229.14,249.42 v229.65,248.91 | v233.21,245.35 235.75,242.81 244.38,242.81 244.89,243.32 247.94,243.32 248.45,242.81 250.99,242.81 251.5,243.32 255.05,243.32 255.56,242.81 257.08,242.81 257.59,243.32 260.64,243.32 261.15,242.81 263.69,242.81 264.2,243.32 267.75,243.32 268.26,242.81 269.78,242.81 270.29,243.32 273.34,243.32 273.85,242.81 v275.37,242.81 | v276.39,247.38 278.42,249.42 291.63,249.42 293.15,250.94 294.68,250.94 296.2,249.42 299.25,249.42 v299.76,249.92
  Route2 0.254: v122.46,247.38 130.59,255.51 132.62,255.51 v133.64,254.5 | v233.21,245.35 v229.65,248.91 | v299.76,249.92 301.79,251.96 301.79,255.51 302.8,256.53 A07.H1
  Route15 0.254: v155.99,275.83 160.06,279.9 v164.12,275.83
  Bottom 0.254: v84.87,249.42 85.38,248.91 85.38,246.37 78.78,239.76 78.78,236.72 77.76,235.7 A23.R2 | v96.56,250.43 v94.52,248.4 | v153.45,254.5 155.48,256.53 155.48,270.75 153.96,272.28 153.96,273.8 v155.99,275.83 | v164.12,275.83 165.14,275.83 168.18,272.78 171.74,272.78 171.74,264.15 177.84,258.05 v177.84,257.54 | v180.88,256.53 181.9,255.51 186.98,255.51 186.98,244.34 186.47,243.83 186.47,242.81 187.49,241.8 187.49,236.72 v188.5,235.7 | v195.11,235.7 196.63,237.22 196.63,240.27 v196.12,240.78 | v208.32,247.38 v205.27,244.34 | v275.37,242.81 276.39,243.83 v276.39,247.38
07\  (via drill 0.61)
  Top 0.254: v85.38,227.06 v81.32,227.06 | v104.18,252.46 104.68,252.97 108.24,252.97 108.75,252.46 v119.92,252.46 | v126.02,244.84 128.05,242.81 136.18,242.81 v138.21,244.84 | v140.75,247.38 142.28,248.91 160.56,248.91 v161.07,248.4 | v164.12,263.13 167.68,266.69 170.72,266.69 172.25,268.21 173.77,268.21 v174.79,267.2 | v274.86,293.61 v276.9,293.61 | v299.25,265.16 301.28,263.13 301.28,260.59 v302.8,260.59
  Route2 0.254: v91.98,238.24 91.98,239.76 101.64,249.42 102.14,249.42 102.65,249.92 102.65,250.94 v104.18,252.46 | v140.75,247.38 v138.21,244.84 | v183.42,266.18 183.42,266.69 184.95,268.21 190.54,268.21 194.09,271.77 194.6,271.77 197.14,274.31 198.16,274.31 v199.68,275.83
  Route15 0.254: v205.78,269.74 208.32,272.28 209.33,272.28 209.84,271.77 212.38,271.77 216.44,275.83 217.46,275.83 236.76,295.14 248.96,282.94 249.97,282.94 250.99,281.93 252,281.93 252.51,281.42 255.05,281.42 256.58,279.9 260.64,279.9 263.69,276.85 v263.69,276.34 | v297.22,282.44 297.22,278.88 293.66,275.32 298.23,270.75 298.23,266.18 v299.25,265.16 | v302.8,260.59 300.77,258.56 300.77,257.54 301.28,257.04 301.28,249.42 300.26,248.4 A07.L1
  Bottom 0.254: v81.32,227.06 81.32,231.13 A23.S2 | v85.38,227.06 91.98,233.67 v91.98,238.24 | v119.92,252.46 120.94,251.45 120.94,249.92 122.46,248.4 123.99,248.4 123.99,246.88 v126.02,244.84 | v161.07,248.4 161.58,248.91 161.58,258.05 161.07,258.56 161.07,260.08 v164.12,263.13 | v174.79,267.2 177.84,267.2 177.84,269.23 180.38,271.77 183.93,271.77 183.93,266.69 v183.42,266.18 | v205.78,269.74 v199.68,275.83 | v263.69,276.34 264.2,276.85 264.2,282.94 v274.86,293.61 | v276.9,293.61 295.69,293.61 297.72,291.58 297.72,288.53 298.23,288.02 298.23,287.01 297.72,286.5 296.71,286.5 296.71,284.47 297.22,283.96 v297.22,282.44
76  (via drill 0.61)
  Top 0.254: v309.41,90.41 313.47,90.41 316.52,87.36 332.78,87.36 334.3,88.89 C04.V2
  Bottom 0.254: v309.41,90.41 308.9,90.41 308.39,90.92 308.39,97.52 308.9,98.03 C06.S2
76+77  (via drill 0.61)
  Top 0.254: v356.65,125.46 361.22,125.46 363.26,127.5 363.76,127.5 364.78,128.51 364.78,131.56 360.72,131.56 v360.21,131.05
  Route2 0.254: v262.67,57.9 263.18,57.9 266.74,61.46 267.75,61.46 270.29,64 270.29,64.5 271.82,66.03 272.32,66.03 273.34,67.04 273.34,67.55 273.85,68.06 274.86,68.06 278.93,72.12 278.93,72.63 279.44,73.14 280.45,73.14 281.47,74.16 282.99,74.16 283.5,74.66 285.02,74.66 296.71,86.35 296.71,87.36 298.23,88.89 298.23,91.43 300.26,93.46 300.77,93.46 322.11,114.8 322.62,114.8 v328.2,120.38 | v330.24,114.8 331.76,114.8 337.35,120.38 338.87,120.38 340.4,121.91 342.43,121.91 346.49,117.84 347.51,118.86 350.05,118.86 v356.65,125.46
  Route15 0.254: v228.13,28.94 233.72,34.53 235.24,33.01 236.76,33.01 238.29,31.48 238.29,30.98 242.35,26.91 249.97,26.91 v262.67,39.61 | v360.21,131.05 359.19,132.07 359.19,134.61 357.67,136.13 C03.C1
  Bottom 0.254: v228.13,28.94 225.59,26.4 225.59,21.32 227.11,19.8 D12.V2 | v262.67,39.61 263.18,40.12 263.18,57.39 v262.67,57.9 | v328.2,120.38 330.24,118.35 v330.24,114.8
76\  (via drill 0.61)
  Top 0.254: v307.88,79.74 310.93,76.7 v311.95,76.7 | v311.95,49.26 316.52,49.26 317.54,48.25 317.54,45.2 317.03,45.2 317.03,42.66 v323.12,42.66 | v322.11,24.37 321.6,23.86 321.09,23.86 312.46,15.23 294.17,15.23 v293.66,15.74 | v292.14,18.28 290.1,20.31 285.53,20.31 282.99,17.77 270.29,17.77 v269.78,18.28 | v260.64,17.26 260.13,16.75 246.42,16.75 245.4,17.77 v243.88,17.77 | v234.22,28.44 233.72,28.94 230.67,28.94 D12.S2
  Route15 0.254: v307.88,87.87 307.88,92.44 306.36,93.97 306.36,94.48 C06.T2 | v311.95,74.16 311.95,71.62 310.93,70.6 310.93,64.5 311.44,64 311.44,55.36 v312.46,54.34 | v234.22,28.44 v240.32,22.34
  Bottom 0.254: D12.S2 229.65,28.94 227.62,30.98 227.62,31.48 D12.R2 | v307.88,79.74 v307.88,87.87 | v311.95,74.16 v311.95,76.7 | v312.46,54.34 313.98,52.82 313.98,49.77 313.47,49.26 v311.95,49.26 | v323.12,42.66 323.63,42.15 323.63,39.61 323.12,39.1 323.12,35.55 323.63,35.04 323.63,33.52 323.12,33.01 323.12,29.45 323.63,28.94 323.63,26.91 322.11,25.39 v322.11,24.37 | v293.66,15.74 292.14,17.26 v292.14,18.28 | v269.78,18.28 268.26,18.28 265.21,15.23 260.64,15.23 v260.64,17.26 | v243.88,17.77 240.32,21.32 v240.32,22.34
77
  Top 0.254: C06.U2 309.92,91.43 310.42,90.92 313.98,90.92 315.5,89.4 318.55,89.4 C05.V2
77\  (via drill 0.61)
  Top 0.254: v294.68,35.55 294.68,33.52 v307.88,33.52 | v307.88,9.13 307.38,9.64 284.52,9.64 v284.01,9.13 | v276.39,21.83 v282.48,21.83 | v255.56,11.16 255.05,10.66 246.42,10.66 245.91,10.15 244.89,10.15 244.38,10.66 240.83,10.66 v239.3,12.18
  Route2 0.254: v306.87,71.62 309.41,69.08 302.3,61.96 302.3,61.46 301.79,60.95 301.79,56.38 299.76,54.34 299.76,52.82 295.69,48.76 295.69,47.74 v294.17,46.22
  Route15 0.254: v239.3,12.18 237.78,12.18 231.18,18.78 v230.67,18.78
  Bottom 0.254: D12.T2 227.62,24.88 227.62,24.37 229.65,22.34 D12.U2 230.67,21.83 v230.67,18.78 | v306.87,71.62 306.87,88.38 C06.V2 | v294.17,46.22 295.18,45.2 295.18,36.06 v294.68,35.55 | v307.88,9.13 v307.88,33.52 | v284.01,9.13 282.48,10.66 v282.48,21.83 | v276.39,21.83 272.83,18.28 272.83,17.77 268.26,13.2 258.61,13.2 258.61,11.67 258.1,11.16 v255.56,11.16
+3V@A09U1  (via drill 0.61)
  Top 0.254: A08.F2 281.47,260.59 282.99,262.12 285.02,262.12 287.06,264.15 287.06,266.18 A08.D1 | 276.39,224.02 275.37,225.03 A09.U1 | v293.15,224.02 276.39,224.02 | A07.T2 294.17,229.1 296.71,229.1 296.71,231.13 A07.S2 297.22,231.13 302.8,231.13 A07.S1 | v222.03,172.2 223.05,171.18 225.08,171.18 225.08,168.64 222.03,165.6 218.48,165.6 217.97,165.09 B13.R1 | v224.06,224.02 241.84,224.02 244.89,220.97 273.34,220.97 276.39,224.02
  Bottom 0.254: A08.F2 280.96,259.58 281.98,258.56 281.98,256.02 282.48,255.51 282.48,252.97 284.01,251.45 A08.K2 284.52,250.43 286.04,248.91 286.04,244.84 289.09,241.8 289.09,235.19 293.15,231.13 293.15,229.1 A07.T2 293.66,228.08 293.66,224.52 v293.15,224.02 | B13.U2 214.41,155.94 215.94,157.47 215.94,160.01 217.46,161.53 217.46,164.07 B13.R1 | v222.03,172.2 222.03,189.98 224.57,192.52 224.57,223.51 v224.06,224.02
+3V@B12U1  (via drill 0.61)
  Top 0.254: B12.U1 235.24,153.91 203.24,153.91 202.22,154.93 B14.U2 | B13.D1 216.95,196.08 214.92,196.08 211.87,193.03 211.87,190.49 B13.F2 210.86,189.98 v206.79,189.98 | B13.K1 220,180.84 218.98,181.85 203.24,181.85 202.22,180.84 B14.K2
  Bottom 0.254: B14.U2 201.71,155.94 203.24,157.47 203.24,160.52 204.76,162.04 204.76,164.07 B14.R1 204.25,165.09 200.19,165.09 200.19,169.66 199.17,170.68 B14.N2 198.66,171.69 200.19,173.22 200.19,177.79 201.2,178.8 201.2,180.33 B14.K2 201.71,181.34 201.71,184.9 v206.79,189.98 206.79,200.65 207.3,201.16 207.3,205.73 B14.A1
+3V@C08U1  (via drill 0.61)
  Top 0.254: C08.U1 291.12,92.44 295.18,92.44 296.2,93.46 316.52,93.46 317.54,92.44 321.6,92.44 C05.U2 322.62,91.43 323.12,90.92 327.7,90.92 328.2,90.41 333.28,90.41 334.81,91.94 337.86,91.94 C04.U2 | C05.N2 319.57,108.19 320.58,109.21 333.28,109.21 334.3,108.19 C04.N2 | C02.C1 370.37,137.15 371.38,138.16 377.48,138.16 379,136.64 382.05,136.64 C01.C1 | 333.79,119.37 336.33,119.37 337.35,120.38 340.9,120.38 C04.J1 341.92,120.89 345.48,120.89 350.05,125.46 351.57,125.46 351.57,128 355.64,132.07 v369.86,132.07 | 333.79,119.37 327.19,119.37 326.17,120.38 C05.J1 | 333.79,119.37 333.79,115.81 334.81,114.8 C04.L2
  Bottom 0.254: C05.N2 319.06,108.7 319.06,113.78 C05.L2 | C04.L2 334.81,113.78 334.81,108.7 C04.N2 335.32,107.18 336.33,106.16 336.33,93.97 337.86,92.44 C04.U2 | v369.86,132.07 369.86,136.13 C02.C1
+3V@C15U1  (via drill 0.61)
  Top 0.254: v194.09,112.26 194.09,114.8 195.62,114.8 197.65,116.83 201.2,116.83 C14.K2 202.22,117.34 207.3,117.34 C14.K1 | C16.H2 176.82,123.94 177.33,124.45 180.88,124.45 181.9,125.46 193.58,125.46 194.6,126.48 198.16,126.48 C14.F2
  Bottom 0.254: v194.09,112.26 194.09,92.95 194.6,92.44 C15.U1 | C14.D1 204.76,134.1 205.78,135.12 205.78,138.67 207.81,140.7 207.81,142.23 C14.A1 | C14.D1 204.25,133.08 201.2,133.08 201.2,132.07 198.66,129.53 198.66,127.5 C14.F2 | C14.K1 208.32,117.84 208.82,118.35 208.82,122.42 209.33,122.92 209.33,124.96 204.76,129.53 204.76,132.58 C14.D1
+3V@D09U1  (via drill 0.61)
  Top 0.254: v294.68,20.82 275.37,20.82 275.37,21.83 D09.U1 | D07.T2 294.17,25.9 294.68,25.9 296.71,27.93 D07.S2 297.22,28.44 302.8,28.44 D07.S1
  Bottom 0.254: v294.68,20.82 294.17,21.32 294.17,24.88 D07.T2
+3V@D10U1
  Top 0.254: D11.K2 243.37,47.74 248.96,47.74 D11.K1 249.46,47.23 252,44.69 D10.L2 | D11.D1 245.91,62.98 245.91,58.92 241.84,58.92 240.32,57.39 D11.F2 | D14.M1 208.82,41.14 211.87,41.14 213.4,42.66 252,42.66 253.53,41.14 255.05,41.14 D10.M2
  Bottom 0.254: D10.N2 252.51,38.6 252.51,43.68 D10.L2 253.02,44.18 254.04,43.17 255.05,43.17 255.05,41.64 D10.M2 256.07,40.63 256.07,38.09 257.59,36.56 257.59,30.47 260.13,27.93 260.13,24.37 261.66,22.85 D10.U1 | D11.F2 239.81,56.38 239.81,52.82 242.86,49.77 242.86,48.25 D11.K2
-15V  (via drill 0.61)
  Top 0.635: 116.88,201.66 118.4,203.19 B20.B2 | 116.37,201.66 111.29,201.66 110.78,201.16 107.73,201.16 106.72,202.17 103.67,202.17 B21.B2 102.65,202.68 101.64,201.66 98.59,201.66 98.08,201.16 95.03,201.16 94.02,202.17 90.97,202.17 B22.B2 89.95,202.68 87.92,202.68 86.4,201.16 83.35,201.16 82.84,201.66 78.78,201.66 78.27,202.17 B23.B2 77.25,203.19 76.74,203.7 73.7,203.7 73.7,202.17 69.63,198.11 57.95,198.11 57.44,198.62 54.39,198.62 53.38,197.6 50.84,197.6 50.84,191.5 v55.92,186.42 | 116.37,201.66 116.88,201.66 | 116.88,201.66 139.23,201.66 140.75,203.19 B18.B2 | AB01.AF2 373.42,261.1 375.45,263.13 375.96,263.13 AB01.AE2 | A23.B2 78.27,273.29 81.82,273.29 83.35,274.82 86.4,274.82 87.92,273.29 89.95,273.29 A22.B2 90.97,273.29 93.51,273.29 95.03,274.82 98.08,274.82 98.59,274.31 101.64,274.31 102.65,273.29 A21.B2 103.67,273.29 106.21,273.29 107.73,274.82 110.78,274.82 111.29,274.31 117.38,274.31 118.4,273.29 A20.B2 119.42,273.8 122.46,273.8 123.48,274.82 126.53,274.82 127.04,274.31 129.07,274.31 129.58,274.82 132.62,274.82 133.13,274.31 135.67,274.31 136.18,274.82 139.23,274.82 140.24,273.8 143.29,273.8 143.8,273.29 A18.B2 | v372.91,279.39 294.17,279.39 293.66,278.88 224.06,278.88 223.56,279.39 200.19,279.39 199.68,278.88 146.85,278.88 146.34,279.39 144.82,279.39 v144.31,279.9 | 116.37,201.66 v116.37,202.68 | v170.72,68.06 174.28,68.06 174.79,68.57 176.82,68.57 177.33,68.06 180.38,68.06 180.88,68.57 183.42,68.57 183.93,68.06 186.98,68.06 187.49,68.57 189.52,68.57 190.03,68.06 193.08,68.06 193.58,68.57 197.14,68.57 198.16,69.58 D14.B2
  Top 0.635: v144.82,81.27 v149.39,81.27 | v142.28,88.38 138.21,92.44 v137.7,92.44 | v132.12,98.03 127.04,103.11 111.29,103.11 v109.26,105.14 | v101.64,122.92 101.64,128.51 v53.38,128.51 | v51.34,139.18 51.34,141.72 v49.82,141.72 | v50.84,169.15 50.84,177.79 v51.85,177.79
  Route2 0.635: v170.72,68.06 167.68,65.01 165.64,65.01 v149.39,81.27 | v132.12,98.03 v137.7,92.44 | v51.85,177.79 57.44,183.38 57.44,184.9 v55.92,186.42
  Route15 0.635: v103.67,110.73 v109.26,105.14 | v48.3,149.85 49.31,150.86 50.33,150.86 v52.36,152.9
  Bottom 0.635: AB01.AE2 375.96,264.15 375.96,266.69 374.43,268.21 374.43,271.26 373.42,272.28 AB01.AB2 372.91,273.8 v372.91,279.39 | v144.31,279.9 144.31,273.8 A18.B2 | v116.37,202.68 116.37,269.74 118.91,272.28 A20.B2 | v144.82,81.27 142.28,83.81 v142.28,88.38 | v103.67,110.73 101.64,112.76 v101.64,122.92 | v53.38,128.51 50.84,128.51 50.84,138.67 v51.34,139.18 | v49.82,141.72 48.8,142.74 48.8,149.34 v48.3,149.85 | v52.36,152.9 50.84,154.42 v50.84,169.15
ADDR_ACC  (via drill 0.61)
  Top 0.254: v191.55,81.78 192.06,82.28 208.32,82.28 v208.82,82.79 | v240.83,81.27 241.84,80.25 244.89,80.25 245.91,79.24 v256.58,79.24 | v296.71,84.32 297.22,83.81 308.9,83.81 v310.42,82.28 | v344.46,84.32 344.97,83.81 v351.06,83.81
  Route2 0.254: v324.65,74.16 324.65,75.17 334.3,84.82 341.92,84.82 343.44,83.3 v344.46,84.32 | v353.6,80.76 356.14,80.76 356.65,81.27 356.65,84.82 360.21,88.38 C02.V2
  Route15 0.254: v164.12,105.14 166.15,103.11 167.68,103.11 177.84,92.95 177.84,91.43 178.34,90.92 179.87,90.92 183.93,86.86 186.47,86.86 v191.55,81.78 | v208.82,82.79 214.41,77.2 223.56,77.2 226.1,74.66 228.13,74.66 230.67,77.2 233.72,77.2 238.29,81.78 238.29,82.28 239.3,83.3 240.83,81.78 v240.83,81.27 | v256.58,79.24 264.7,87.36 269.28,87.36 271.31,85.33 272.32,85.33 273.34,86.35 273.34,87.36 272.83,87.87 272.83,88.89 274.36,90.41 277.4,90.41 280.45,87.36 281.47,87.36 283.5,85.33 288.07,85.33 288.58,84.82 296.2,84.82 v296.71,84.32 | v310.42,82.28 316.52,82.28 v324.65,74.16
  Bottom 0.254: v164.12,105.14 164.12,106.67 163.61,107.18 C17.N1 | v351.06,83.81 353.6,81.27 v353.6,80.76
ADDR_ACC\  (via drill 0.61)
  Top 0.254: v178.34,105.14 177.33,106.16 175.3,106.16 174.79,105.65 167.68,105.65 167.17,105.14 C17.P1 | v188.5,102.1 189.52,103.11 v197.65,103.11
  Route2 0.254: v197.65,103.11 200.19,103.11 201.71,101.59 202.73,102.6 202.73,103.62 203.24,104.13 203.24,108.7 213.4,118.86 221.52,118.86 222.03,119.37 229.14,119.37 229.65,119.88 231.68,119.88 233.21,118.35 234.22,118.35 235.75,119.88 235.75,120.38 v239.3,123.94 | v243.88,126.99 251.5,134.61 257.59,134.61 267.24,144.26 269.78,144.26 279.44,153.91 279.44,154.42 280.45,155.44 280.96,155.44 281.47,155.94 281.47,157.98 B08.T2
  Route15 0.254: v178.34,105.14 179.87,105.14 181.9,103.11 187.49,103.11 v188.5,102.1
  Bottom 0.254: v239.3,123.94 241.34,123.94 241.34,124.45 v243.88,126.99
B-BRK  (via drill 0.61)
  Top 0.254: v238.29,155.94 239.3,156.96 250.99,156.96 B10.T2 253.02,157.98 253.53,157.98 255.56,155.94 B10.U2 256.07,154.93 258.1,154.93 263.69,149.34 v384.59,149.34
  Bottom 0.254: v238.29,155.94 238.29,64.5 235.24,61.46 235.24,42.66 236.26,41.64 D12.M1 | v384.59,149.34 384.59,132.07 383.07,130.54 C01.E1 | B10.R2 252,164.07 252,158.99 B10.T2 | B10.S2 255.56,161.02 255.56,155.94 B10.U2
B-BRK\  (via drill 0.61)
  Top 0.254: B02.M2 364.27,174.23 366.3,174.23 368.34,172.2 369.35,172.2 369.35,168.64 B02.P1 369.86,167.63 369.86,163.56 368.34,163.56 365.8,161.02 364.78,161.02 363.26,159.5 360.72,159.5 B02.T2 359.7,158.48 v358.18,158.48 | B02.J1 366.3,184.39 365.29,185.41 360.72,185.41 360.72,189.98 B02.F2 360.72,191 363.76,191 364.78,192.01 368.34,192.01 368.34,194.55 v369.35,195.57 | v358.18,148.32 357.67,148.83 298.74,148.83 296.71,146.8 275.88,146.8 274.36,148.32 248.96,148.32 248.45,147.82 246.92,147.82 246.92,149.34 247.43,149.85 250.48,149.85 252,151.37 B10.V2
  Bottom 0.254: B02.M2 363.76,175.25 364.27,175.76 364.27,178.8 366.3,180.84 366.3,183.88 B02.J1 | v369.35,195.57 369.35,199.63 B02.C1 | v358.18,148.32 358.68,148.83 358.68,157.98 v358.18,158.48
B-RUN  (via drill 0.61)
  Top 0.254: v365.29,7.61 363.26,5.58 325.66,5.58 324.65,6.59 298.74,6.59 298.23,6.08 v296.71,6.08 | v294.68,8.12 v288.07,8.12 | v267.75,26.91 v254.54,26.91 | v204.76,74.66 v199.17,74.66 | v199.17,84.32 198.66,84.82 v195.11,84.82
  Route2 0.254: v195.11,89.4 196.63,90.92 196.63,103.62 199.68,106.67 199.68,111.24 201.2,112.76 205.78,112.76 209.33,116.32 209.33,117.84 209.84,118.35 211.36,118.35 215.94,122.92 215.94,127.5 217.97,129.53 217.97,131.56 222.03,135.62 222.03,140.2 222.54,140.7 222.54,152.39 227.11,156.96 227.62,156.96 233.21,162.55 233.21,163.56 234.73,163.56 237.78,166.61 237.78,169.15 B11.N2
  Route15 0.254: v379.51,135.62 381.04,135.62 381.54,135.12 381.54,133.59 384.08,131.05 384.08,126.48 385.1,125.46 385.1,123.94 380.02,118.86 380.02,115.81 381.04,114.8 381.04,108.7 384.08,105.65 384.08,100.06 384.59,99.56 384.59,59.42 376.46,51.3 380.02,47.74 380.02,46.22 381.04,45.2 381.04,43.68 v380.02,42.66 | v288.07,8.12 276.39,19.8 273.34,19.8 v270.29,22.85 | v247.43,27.93 245.91,27.93 240.83,33.01 237.78,33.01 237.27,33.52 235.75,33.52 235.24,34.02 235.24,36.06 234.73,36.56 232.7,36.56 225.59,43.68 225.59,45.71 216.95,54.34 216.95,54.85 v208.82,62.98
  Bottom 0.254: v379.51,135.62 379.51,139.18 C01.B1 | v380.02,42.66 377.99,40.63 377.99,34.53 377.48,34.02 377.48,19.8 v365.29,7.61 | v296.71,6.08 v294.68,8.12 | v270.29,22.85 267.75,25.39 v267.75,26.91 | v254.54,26.91 252,26.91 251.5,27.42 249.97,27.42 249.97,26.91 247.43,26.91 v247.43,27.93 | v208.82,62.98 206.79,65.01 206.79,72.63 v204.76,74.66 | v199.17,74.66 v199.17,84.32 | v195.11,84.82 v195.11,89.4
B-XSTA  (via drill 0.61)
  Top 0.254: v240.83,65.01 239.3,65.01 238.29,64 236.76,64 236.76,60.95 D12.E1 | v245.91,99.56 244.38,101.08 v242.86,101.08 240.83,103.11 239.3,103.11 238.8,102.6 237.27,102.6 234.73,100.06 232.19,100.06 v230.67,101.59 | v252.51,263.64 255.05,263.64 A10.E2 | v236.76,253.48 231.18,247.89 229.14,247.89 228.13,248.91 225.59,248.91 v225.08,248.4
  Route2 0.254: v252.51,263.64 249.97,266.18 248.45,266.18 240.32,258.05 v239.81,258.05 | v225.08,248.4 224.06,247.38 224.06,245.86 223.05,244.84 223.05,242.81 221.02,240.78 219.49,240.78 208.82,230.11 208.32,230.11 204.25,226.05 204.25,225.54 v201.2,222.49 | v201.2,207.76 200.7,207.76 197.14,204.2 197.14,199.12 194.6,196.58 194.6,195.06 194.09,194.55 194.09,192.52 193.58,192.01 191.55,192.01 v176.82,177.28
  Route15 0.254: v176.82,177.28 v179.87,174.23 | v178.34,168.14 186.98,159.5 186.98,153.4 197.14,143.24 197.14,142.74 198.66,141.21 199.17,141.21 200.19,140.2 200.19,139.69 201.71,138.16 202.22,138.16 206.28,134.1 206.28,132.58 204.76,131.05 204.76,129.53 210.86,123.43 212.38,123.43 220,115.81 221.52,115.81 228.13,109.21 228.13,104.13 v230.67,101.59
  Bottom 0.254: v240.83,65.01 241.34,65.52 241.34,69.08 244.38,72.12 245.91,72.12 245.91,79.24 245.4,79.74 245.4,87.36 244.38,88.38 244.38,96.51 245.91,98.03 v245.91,99.56 | v242.86,101.08 242.86,104.13 C11.P2 | v239.81,258.05 236.76,255 v236.76,253.48 | v201.2,222.49 201.71,221.98 201.71,211.82 202.22,211.32 202.22,208.78 v201.2,207.76 | v179.87,174.23 177.84,172.2 177.84,168.64 v178.34,168.14
BAC_00  (via drill 0.61)
  Top 0.254: v303.31,196.58 300.77,196.58 B07.D1 | B06.B1 312.46,202.68 309.41,202.68 306.87,200.14 303.82,200.14 B07.C1
  Bottom 0.254: v303.31,196.58 303.31,199.12 B07.C1
BAC_00\  (via drill 0.61)
  Top 0.254: v257.08,38.6 255.05,36.56 251.5,36.56 249.97,38.09 248.45,38.09 243.88,33.52 233.21,33.52 232.7,33.01 226.1,33.01 v225.08,31.99 | v223.56,11.16 223.05,10.66 205.27,10.66 204.25,11.67 190.03,11.67 189.01,10.66 132.62,10.66 131.61,11.67 124.5,11.67 122.97,13.2 93,13.2 v92.49,13.7 | v97.06,233.16 97.57,233.67 v112.3,233.67 | v114.34,288.02 115.35,289.04 139.74,289.04 141.77,291.07 159.55,291.07 160.06,290.56 161.07,290.56 162.09,289.55 208.32,289.55 215.43,296.66 240.32,296.66 242.35,294.63 292.64,294.63 293.15,295.14 295.69,295.14 v296.2,295.64 | v304.84,206.24 306.87,204.2 v308.9,204.2 | v309.92,201.66 313.98,201.66 315.5,203.19 315.5,204.71 | 315.5,204.71 315.5,205.73 B06.A1 | v353.6,146.8 353.1,146.29 341.41,146.29 340.4,147.31 338.36,147.31 v337.86,146.8 | v338.36,153.91 338.87,153.91 339.38,154.42 339.38,156.96 335.82,156.96 v335.32,156.45 | v337.86,164.07 v335.32,161.53 | v342.94,179.31 339.89,179.31 338.87,178.3 v338.36,178.3 | v327.19,203.19 327.19,204.71 315.5,204.71
  Route2 0.254: v337.86,164.07 337.86,165.6 336.84,166.61 336.84,170.17 339.89,173.22 340.4,173.22 v341.41,174.23
  Route15 0.254: v332.27,189.98 v337.86,184.39 | v332.27,193.54 327.19,198.62 v327.19,203.19
  Bottom 0.254: v257.08,38.6 257.59,39.1 257.59,55.36 258.61,56.38 D10.F1 | v225.08,31.99 223.05,29.96 223.05,21.83 223.56,21.32 v223.56,11.16 | v92.49,13.7 92.49,189.98 95.54,193.03 95.54,231.64 v97.06,233.16 | v112.3,233.67 114.34,235.7 114.34,257.54 113.32,258.56 113.32,260.08 114.84,261.61 114.84,279.9 114.34,280.4 v114.34,288.02 | v296.2,295.64 301.79,290.06 301.79,221.98 302.8,220.97 302.8,217.41 305.34,214.87 305.34,206.74 v304.84,206.24 | v308.9,204.2 309.92,203.19 v309.92,201.66 | v353.6,146.8 353.6,140.2 C03.B1 | v337.86,146.8 337.86,153.4 v338.36,153.91 | v335.32,156.45 333.79,156.45 333.79,160.01 v335.32,161.53 | v341.41,174.23 342.43,175.25 342.43,176.77 342.94,177.28 v342.94,179.31 | v338.36,178.3 338.87,178.8 338.87,179.31 339.38,179.82 339.38,182.87 v337.86,184.39 | v332.27,193.54 v332.27,189.98
BAC_01
  Top 0.254: B07.F2 294.17,190.49 296.71,193.03 B07.E2 297.22,194.04 298.23,194.04 298.74,194.55 310.93,194.55 311.95,193.54 315.5,193.54 B06.E1
BAC_01\  (via drill 0.61)
  Top 0.254: v260.64,62.98 261.15,62.47 264.2,62.47 264.7,61.96 266.74,61.96 v268.77,64 | v273.34,70.6 273.85,71.11 v284.01,71.11 | v290.61,76.19 291.63,77.2 296.2,77.2 296.71,76.7 v308.39,76.7 | v312.46,97.52 312.96,97.02 318.55,97.02 319.57,98.03 320.58,98.03 321.6,97.02 v329.73,97.02 | v330.74,93.97 339.89,93.97 340.4,93.46 356.14,93.46 v356.65,93.97 | v318.04,193.54 317.03,194.55 315,194.55 313.47,196.08 B06.D1
  Route2 0.254: v271.82,67.04 v268.77,64 | v312.46,97.52 v306.87,91.94 | v318.04,193.54 325.66,185.92 328.2,188.46 329.22,188.46 331.76,191 333.28,191 337.35,195.06 338.87,195.06 v340.9,193.03 | v379.51,169.15 382.56,166.1 381.04,164.58 381.04,163.06 371.89,153.91 371.89,149.34 371.38,148.83 371.38,141.72 364.78,135.12 363.76,135.12 362.24,133.59 362.24,132.58 361.73,132.07 359.19,132.07 357.67,130.54 C03.E1
  Route15 0.254: v358.18,108.19 364.78,114.8 364.78,119.88 359.19,125.46 359.19,128 357.67,129.53 C03.E1 | v340.9,193.03 341.92,193.03 345.48,196.58 346.49,195.57 352.59,195.57 354.62,193.54 355.13,193.54 366.3,182.36 366.3,180.33 372.91,173.72 374.94,173.72 v379.51,169.15
  Bottom 0.254: v260.64,62.98 260.64,55.36 261.66,54.34 D10.H1 | v271.82,67.04 273.34,68.57 v273.34,70.6 | v284.01,71.11 285.53,71.11 285.53,71.62 288.07,71.62 288.07,73.65 v290.61,76.19 | v308.39,76.7 308.9,77.2 308.9,88.38 306.87,90.41 v306.87,91.94 | v329.73,97.02 330.74,96 v330.74,93.97 | v356.65,93.97 358.68,96 358.68,105.65 358.18,106.16 v358.18,108.19
BAC_02  (via drill 0.61)
  Top 0.254: B07.J1 300.77,183.88 304.33,183.88 305.85,185.41 310.93,185.41 311.95,186.42 315.5,186.42 B06.H1 | v299.76,180.84 302.8,180.84 B07.K1
  Bottom 0.254: v299.76,180.84 299.76,183.38 B07.J1
BAC_02\  (via drill 0.61)
  Top 0.254: v273.85,31.99 274.36,31.48 278.93,31.48 279.94,30.47 281.98,30.47 285.53,34.02 v287.06,34.02 | v290.61,37.58 292.64,39.61 294.17,39.61 296.71,37.07 297.72,37.07 298.74,38.09 298.74,42.66 308.39,42.66 v308.9,43.17 | v324.65,53.33 325.66,54.34 326.17,54.34 329.73,57.9 333.28,57.9 334.3,58.92 334.81,58.92 336.33,60.44 v336.33,60.95 | v350.56,76.7 352.59,78.73 352.59,81.78 v355.64,81.78 | v352.59,125.97 354.62,123.94 356.65,123.94 C03.H1 | v350.56,115.81 352.08,115.81 v354.11,117.84
  Route2 0.254: v287.06,34.02 v290.61,37.58 | v309.92,45.2 311.95,47.23 313.47,47.23 315.5,49.26 320.58,49.26 v324.65,53.33 | v336.33,60.95 339.38,64 339.89,64 340.4,64.5 340.4,66.54 v350.56,76.7
  Route15 0.254: v262.67,38.09 263.18,38.09 267.75,33.52 272.32,33.52 v273.85,31.99 | v355.64,88.89 355.64,90.41 354.62,91.43 354.62,91.94 352.59,93.97 352.59,97.52 v353.1,98.03 | v313.47,179.31 313.98,178.8 313.98,174.74 314.49,174.23 314.49,165.09 320.58,158.99 320.58,149.34 324.14,145.78 324.14,138.67 330.74,132.07 332.27,132.07 347.51,116.83 349.03,116.83 350.05,115.81 v350.56,115.81
  Bottom 0.254: v262.67,38.09 260.64,40.12 260.64,48.76 259.12,50.28 D10.J1 | v308.9,43.17 309.92,44.18 v309.92,45.2 | v355.64,81.78 v355.64,88.89 | v353.1,98.03 352.59,98.54 352.59,117.84 | 352.59,117.84 v352.59,125.97 | v313.47,179.31 313.98,179.82 313.98,184.9 312.46,186.42 312.46,189.47 B06.F1 | 352.59,117.84 v354.11,117.84
BAC_03
  Top 0.254: B07.N2 294.17,171.69 296.2,173.72 296.71,173.72 B07.M2 297.22,174.74 298.23,175.76 307.88,175.76 312.46,180.33 315.5,180.33 B06.K1
BAC_03\  (via drill 0.61)
  Top 0.254: v254.54,44.18 256.58,44.18 256.58,46.22 258.1,47.74 261.66,47.74 D10.K1 | v257.59,12.18 258.1,12.69 275.88,12.69 276.39,13.2 277.4,13.2 278.42,12.18 332.78,12.18 v333.28,11.67 | v333.28,60.95 332.78,61.46 v329.73,61.46 | v315.5,183.38 313.47,183.38 B06.J1
  Route2 0.254: v329.73,70.6 329.73,78.73 v334.81,83.81 | v336.84,90.92 336.84,93.46 346.49,103.11 348.02,103.11 348.52,103.62 348.52,104.64 v357.67,113.78 | v363.26,125.97 359.19,121.91 359.19,119.37 357.67,117.84 C03.K1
